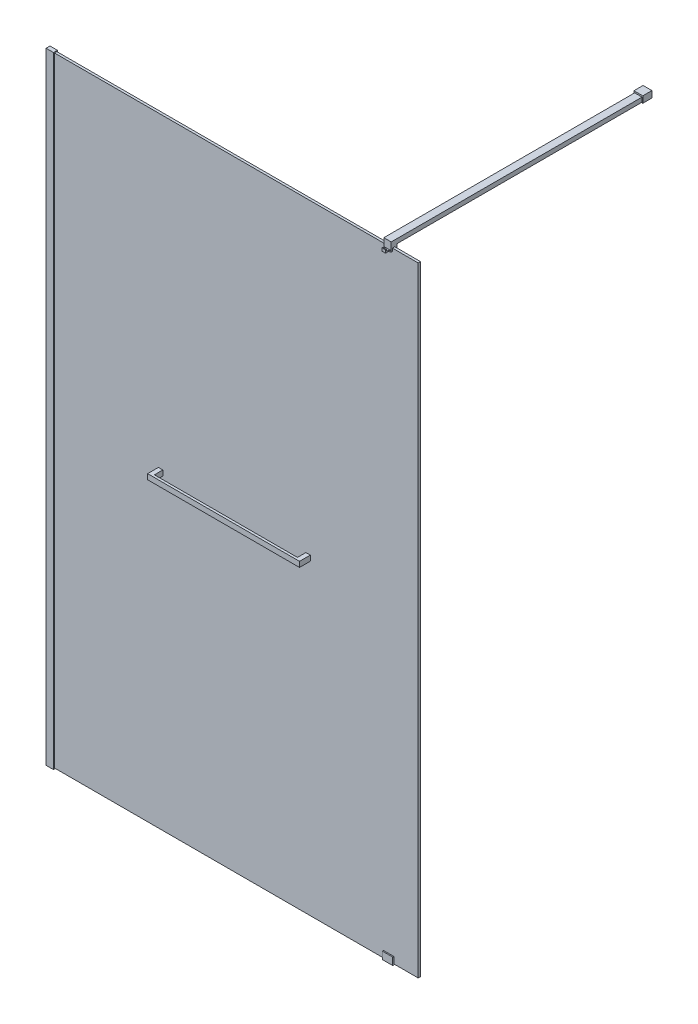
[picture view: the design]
ISO-10303-21;
HEADER;
FILE_DESCRIPTION(('STEP AP214'),'2;1');
FILE_NAME('part.step','',(''),(''),'','','');
FILE_SCHEMA(('AUTOMOTIVE_DESIGN { 1 0 10303 214 1 1 1 1 }'));
ENDSEC;
DATA;
#1=APPLICATION_CONTEXT('core data for automotive mechanical design processes');
#2=APPLICATION_PROTOCOL_DEFINITION('international standard','automotive_design',2000,#1);
#3=PRODUCT_CONTEXT('',#1,'mechanical');
#4=PRODUCT('Part','Part','',(#3));
#5=PRODUCT_RELATED_PRODUCT_CATEGORY('part','',(#4));
#6=PRODUCT_DEFINITION_FORMATION('','',#4);
#7=PRODUCT_DEFINITION_CONTEXT('part definition',#1,'design');
#8=PRODUCT_DEFINITION('design','',#6,#7);
#9=PRODUCT_DEFINITION_SHAPE('','',#8);
#10=(LENGTH_UNIT() NAMED_UNIT(*) SI_UNIT(.MILLI.,.METRE.));
#11=(NAMED_UNIT(*) PLANE_ANGLE_UNIT() SI_UNIT($,.RADIAN.));
#12=(NAMED_UNIT(*) SI_UNIT($,.STERADIAN.) SOLID_ANGLE_UNIT());
#13=UNCERTAINTY_MEASURE_WITH_UNIT(LENGTH_MEASURE(1.E-05),#10,'distance_accuracy_value','');
#14=(GEOMETRIC_REPRESENTATION_CONTEXT(3) GLOBAL_UNCERTAINTY_ASSIGNED_CONTEXT((#13)) GLOBAL_UNIT_ASSIGNED_CONTEXT((#10,
#11,#12)) REPRESENTATION_CONTEXT('',''));
#15=CARTESIAN_POINT('',(0.,0.,0.));
#16=DIRECTION('',(0.,0.,1.));
#17=DIRECTION('',(1.,0.,0.));
#18=AXIS2_PLACEMENT_3D('',#15,#16,#17);
#19=CARTESIAN_POINT('',(392.45,1059.,-21.4));
#20=DIRECTION('',(1.,0.,0.));
#21=DIRECTION('',(0.,0.,-1.));
#22=AXIS2_PLACEMENT_3D('',#19,#20,#21);
#23=PLANE('',#22);
#24=DIRECTION('',(0.,1.,0.));
#25=VECTOR('',#24,1.);
#26=CARTESIAN_POINT('',(392.45,1059.,25.1));
#27=LINE('',#26,#25);
#28=CARTESIAN_POINT('',(392.45,1041.,25.1));
#29=VERTEX_POINT('',#28);
#30=CARTESIAN_POINT('',(392.45,1059.,25.1));
#31=VERTEX_POINT('',#30);
#32=EDGE_CURVE('E63',#29,#31,#27,.T.);
#33=ORIENTED_EDGE('',*,*,#32,.F.);
#34=DIRECTION('',(0.,0.,1.));
#35=VECTOR('',#34,1.);
#36=CARTESIAN_POINT('',(392.45,1041.,-21.4));
#37=LINE('',#36,#35);
#38=CARTESIAN_POINT('',(392.45,1041.,-21.4));
#39=VERTEX_POINT('',#38);
#40=EDGE_CURVE('E12',#39,#29,#37,.T.);
#41=ORIENTED_EDGE('',*,*,#40,.F.);
#42=DIRECTION('',(0.,1.,0.));
#43=VECTOR('',#42,1.);
#44=CARTESIAN_POINT('',(392.45,1059.,-21.4));
#45=LINE('',#44,#43);
#46=CARTESIAN_POINT('',(392.45,1059.,-21.4));
#47=VERTEX_POINT('',#46);
#48=EDGE_CURVE('E193',#39,#47,#45,.T.);
#49=ORIENTED_EDGE('',*,*,#48,.T.);
#50=DIRECTION('',(0.,0.,1.));
#51=VECTOR('',#50,1.);
#52=CARTESIAN_POINT('',(392.45,1059.,-21.4));
#53=LINE('',#52,#51);
#54=EDGE_CURVE('E176',#47,#31,#53,.T.);
#55=ORIENTED_EDGE('',*,*,#54,.T.);
#56=EDGE_LOOP('',(#33,#41,#49,#55));
#57=FACE_BOUND('',#56,.T.);
#58=ADVANCED_FACE('F46',(#57),#23,.T.);
#59=CARTESIAN_POINT('',(377.45,1041.,-21.4));
#60=DIRECTION('',(0.,-1.,0.));
#61=DIRECTION('',(0.,0.,-1.));
#62=AXIS2_PLACEMENT_3D('',#59,#60,#61);
#63=PLANE('',#62);
#64=ORIENTED_EDGE('',*,*,#40,.T.);
#65=DIRECTION('',(-1.,0.,0.));
#66=VECTOR('',#65,1.);
#67=CARTESIAN_POINT('',(897.147715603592,1041.,25.1));
#68=LINE('',#67,#66);
#69=CARTESIAN_POINT('',(877.45,1041.,25.1));
#70=VERTEX_POINT('',#69);
#71=EDGE_CURVE('E166',#70,#29,#68,.T.);
#72=ORIENTED_EDGE('',*,*,#71,.F.);
#73=DIRECTION('',(0.,0.,1.));
#74=VECTOR('',#73,1.);
#75=CARTESIAN_POINT('',(877.45,1041.,-21.4));
#76=LINE('',#75,#74);
#77=CARTESIAN_POINT('',(877.45,1041.,-21.4));
#78=VERTEX_POINT('',#77);
#79=EDGE_CURVE('E149',#78,#70,#76,.T.);
#80=ORIENTED_EDGE('',*,*,#79,.F.);
#81=DIRECTION('',(1.,0.,0.));
#82=VECTOR('',#81,1.);
#83=CARTESIAN_POINT('',(877.45,1041.,-21.4));
#84=LINE('',#83,#82);
#85=CARTESIAN_POINT('',(892.45,1041.,-21.4));
#86=VERTEX_POINT('',#85);
#87=EDGE_CURVE('E131',#78,#86,#84,.T.);
#88=ORIENTED_EDGE('',*,*,#87,.T.);
#89=DIRECTION('',(0.,0.,1.));
#90=VECTOR('',#89,1.);
#91=CARTESIAN_POINT('',(892.45,1041.,-21.4));
#92=LINE('',#91,#90);
#93=CARTESIAN_POINT('',(892.45,1041.,33.1));
#94=VERTEX_POINT('',#93);
#95=EDGE_CURVE('E147',#86,#94,#92,.T.);
#96=ORIENTED_EDGE('',*,*,#95,.T.);
#97=DIRECTION('',(1.,0.,0.));
#98=VECTOR('',#97,1.);
#99=CARTESIAN_POINT('',(377.45,1041.,33.1));
#100=LINE('',#99,#98);
#101=CARTESIAN_POINT('',(377.45,1041.,33.1));
#102=VERTEX_POINT('',#101);
#103=EDGE_CURVE('E135',#102,#94,#100,.T.);
#104=ORIENTED_EDGE('',*,*,#103,.F.);
#105=DIRECTION('',(0.,0.,1.));
#106=VECTOR('',#105,1.);
#107=CARTESIAN_POINT('',(377.45,1041.,-21.4));
#108=LINE('',#107,#106);
#109=CARTESIAN_POINT('',(377.45,1041.,-21.4));
#110=VERTEX_POINT('',#109);
#111=EDGE_CURVE('E55',#110,#102,#108,.T.);
#112=ORIENTED_EDGE('',*,*,#111,.F.);
#113=DIRECTION('',(1.,0.,0.));
#114=VECTOR('',#113,1.);
#115=CARTESIAN_POINT('',(377.45,1041.,-21.4));
#116=LINE('',#115,#114);
#117=EDGE_CURVE('E181',#110,#39,#116,.T.);
#118=ORIENTED_EDGE('',*,*,#117,.T.);
#119=EDGE_LOOP('',(#64,#72,#80,#88,#96,#104,#112,#118));
#120=FACE_BOUND('',#119,.T.);
#121=ADVANCED_FACE('F197',(#120),#63,.T.);
#122=CARTESIAN_POINT('',(377.45,1059.,-21.4));
#123=DIRECTION('',(-1.,0.,0.));
#124=DIRECTION('',(0.,0.,1.));
#125=AXIS2_PLACEMENT_3D('',#122,#123,#124);
#126=PLANE('',#125);
#127=ORIENTED_EDGE('',*,*,#111,.T.);
#128=DIRECTION('',(0.,-1.,0.));
#129=VECTOR('',#128,1.);
#130=CARTESIAN_POINT('',(377.45,1059.,33.1));
#131=LINE('',#130,#129);
#132=CARTESIAN_POINT('',(377.45,1059.,33.1));
#133=VERTEX_POINT('',#132);
#134=EDGE_CURVE('E121',#133,#102,#131,.T.);
#135=ORIENTED_EDGE('',*,*,#134,.F.);
#136=DIRECTION('',(0.,0.,1.));
#137=VECTOR('',#136,1.);
#138=CARTESIAN_POINT('',(377.45,1059.,-21.4));
#139=LINE('',#138,#137);
#140=CARTESIAN_POINT('',(377.45,1059.,-21.4));
#141=VERTEX_POINT('',#140);
#142=EDGE_CURVE('E116',#141,#133,#139,.T.);
#143=ORIENTED_EDGE('',*,*,#142,.F.);
#144=DIRECTION('',(0.,-1.,0.));
#145=VECTOR('',#144,1.);
#146=CARTESIAN_POINT('',(377.45,1059.,-21.4));
#147=LINE('',#146,#145);
#148=EDGE_CURVE('E186',#141,#110,#147,.T.);
#149=ORIENTED_EDGE('',*,*,#148,.T.);
#150=EDGE_LOOP('',(#127,#135,#143,#149));
#151=FACE_BOUND('',#150,.T.);
#152=ADVANCED_FACE('F218',(#151),#126,.T.);
#153=CARTESIAN_POINT('',(377.45,1059.,-21.4));
#154=DIRECTION('',(0.,1.,0.));
#155=DIRECTION('',(0.,0.,1.));
#156=AXIS2_PLACEMENT_3D('',#153,#154,#155);
#157=PLANE('',#156);
#158=ORIENTED_EDGE('',*,*,#142,.T.);
#159=DIRECTION('',(-1.,0.,0.));
#160=VECTOR('',#159,1.);
#161=CARTESIAN_POINT('',(377.45,1059.,33.1));
#162=LINE('',#161,#160);
#163=CARTESIAN_POINT('',(892.45,1059.,33.1));
#164=VERTEX_POINT('',#163);
#165=EDGE_CURVE('E109',#164,#133,#162,.T.);
#166=ORIENTED_EDGE('',*,*,#165,.F.);
#167=DIRECTION('',(0.,0.,1.));
#168=VECTOR('',#167,1.);
#169=CARTESIAN_POINT('',(892.45,1059.,-21.4));
#170=LINE('',#169,#168);
#171=CARTESIAN_POINT('',(892.45,1059.,-21.4));
#172=VERTEX_POINT('',#171);
#173=EDGE_CURVE('E113',#172,#164,#170,.T.);
#174=ORIENTED_EDGE('',*,*,#173,.F.);
#175=DIRECTION('',(-1.,0.,0.));
#176=VECTOR('',#175,1.);
#177=CARTESIAN_POINT('',(877.45,1059.,-21.4));
#178=LINE('',#177,#176);
#179=CARTESIAN_POINT('',(877.45,1059.,-21.4));
#180=VERTEX_POINT('',#179);
#181=EDGE_CURVE('E138',#172,#180,#178,.T.);
#182=ORIENTED_EDGE('',*,*,#181,.T.);
#183=DIRECTION('',(0.,0.,1.));
#184=VECTOR('',#183,1.);
#185=CARTESIAN_POINT('',(877.45,1059.,-21.4));
#186=LINE('',#185,#184);
#187=CARTESIAN_POINT('',(877.45,1059.,25.1));
#188=VERTEX_POINT('',#187);
#189=EDGE_CURVE('E130',#180,#188,#186,.T.);
#190=ORIENTED_EDGE('',*,*,#189,.T.);
#191=DIRECTION('',(-1.,0.,0.));
#192=VECTOR('',#191,1.);
#193=CARTESIAN_POINT('',(897.147715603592,1059.,25.1));
#194=LINE('',#193,#192);
#195=EDGE_CURVE('E163',#188,#31,#194,.T.);
#196=ORIENTED_EDGE('',*,*,#195,.T.);
#197=ORIENTED_EDGE('',*,*,#54,.F.);
#198=DIRECTION('',(-1.,0.,0.));
#199=VECTOR('',#198,1.);
#200=CARTESIAN_POINT('',(377.45,1059.,-21.4));
#201=LINE('',#200,#199);
#202=EDGE_CURVE('E190',#47,#141,#201,.T.);
#203=ORIENTED_EDGE('',*,*,#202,.T.);
#204=EDGE_LOOP('',(#158,#166,#174,#182,#190,#196,#197,#203));
#205=FACE_BOUND('',#204,.T.);
#206=ADVANCED_FACE('F111',(#205),#157,.T.);
#207=CARTESIAN_POINT('',(392.45,1041.,-21.4));
#208=DIRECTION('',(0.,0.,1.));
#209=DIRECTION('',(1.,0.,0.));
#210=AXIS2_PLACEMENT_3D('',#207,#208,#209);
#211=PLANE('',#210);
#212=ORIENTED_EDGE('',*,*,#48,.F.);
#213=ORIENTED_EDGE('',*,*,#117,.F.);
#214=ORIENTED_EDGE('',*,*,#148,.F.);
#215=ORIENTED_EDGE('',*,*,#202,.F.);
#216=EDGE_LOOP('',(#212,#213,#214,#215));
#217=FACE_BOUND('',#216,.T.);
#218=ADVANCED_FACE('F225',(#217),#211,.F.);
#219=CARTESIAN_POINT('',(392.45,1041.,33.1));
#220=DIRECTION('',(0.,0.,1.));
#221=DIRECTION('',(1.,0.,0.));
#222=AXIS2_PLACEMENT_3D('',#219,#220,#221);
#223=PLANE('',#222);
#224=ORIENTED_EDGE('',*,*,#103,.T.);
#225=DIRECTION('',(0.,1.,0.));
#226=VECTOR('',#225,1.);
#227=CARTESIAN_POINT('',(892.45,1059.,33.1));
#228=LINE('',#227,#226);
#229=EDGE_CURVE('E127',#94,#164,#228,.T.);
#230=ORIENTED_EDGE('',*,*,#229,.T.);
#231=ORIENTED_EDGE('',*,*,#165,.T.);
#232=ORIENTED_EDGE('',*,*,#134,.T.);
#233=EDGE_LOOP('',(#224,#230,#231,#232));
#234=FACE_BOUND('',#233,.T.);
#235=ADVANCED_FACE('F133',(#234),#223,.T.);
#236=CARTESIAN_POINT('',(897.147715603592,1059.,25.1));
#237=DIRECTION('',(0.,0.,1.));
#238=DIRECTION('',(0.,-1.,0.));
#239=AXIS2_PLACEMENT_3D('',#236,#237,#238);
#240=PLANE('',#239);
#241=ORIENTED_EDGE('',*,*,#195,.F.);
#242=DIRECTION('',(0.,-1.,0.));
#243=VECTOR('',#242,1.);
#244=CARTESIAN_POINT('',(877.45,1059.,25.1));
#245=LINE('',#244,#243);
#246=EDGE_CURVE('E49',#188,#70,#245,.T.);
#247=ORIENTED_EDGE('',*,*,#246,.T.);
#248=ORIENTED_EDGE('',*,*,#71,.T.);
#249=ORIENTED_EDGE('',*,*,#32,.T.);
#250=EDGE_LOOP('',(#241,#247,#248,#249));
#251=FACE_BOUND('',#250,.T.);
#252=ADVANCED_FACE('F203',(#251),#240,.F.);
#253=CARTESIAN_POINT('',(877.45,1059.,-21.4));
#254=DIRECTION('',(-1.,0.,0.));
#255=DIRECTION('',(0.,0.,1.));
#256=AXIS2_PLACEMENT_3D('',#253,#254,#255);
#257=PLANE('',#256);
#258=ORIENTED_EDGE('',*,*,#246,.F.);
#259=ORIENTED_EDGE('',*,*,#189,.F.);
#260=DIRECTION('',(0.,-1.,0.));
#261=VECTOR('',#260,1.);
#262=CARTESIAN_POINT('',(877.45,1059.,-21.4));
#263=LINE('',#262,#261);
#264=EDGE_CURVE('E142',#180,#78,#263,.T.);
#265=ORIENTED_EDGE('',*,*,#264,.T.);
#266=ORIENTED_EDGE('',*,*,#79,.T.);
#267=EDGE_LOOP('',(#258,#259,#265,#266));
#268=FACE_BOUND('',#267,.T.);
#269=ADVANCED_FACE('F204',(#268),#257,.T.);
#270=CARTESIAN_POINT('',(892.45,1059.,-21.4));
#271=DIRECTION('',(1.,0.,0.));
#272=DIRECTION('',(0.,0.,-1.));
#273=AXIS2_PLACEMENT_3D('',#270,#271,#272);
#274=PLANE('',#273);
#275=ORIENTED_EDGE('',*,*,#173,.T.);
#276=ORIENTED_EDGE('',*,*,#229,.F.);
#277=ORIENTED_EDGE('',*,*,#95,.F.);
#278=DIRECTION('',(0.,1.,0.));
#279=VECTOR('',#278,1.);
#280=CARTESIAN_POINT('',(892.45,1059.,-21.4));
#281=LINE('',#280,#279);
#282=EDGE_CURVE('E129',#86,#172,#281,.T.);
#283=ORIENTED_EDGE('',*,*,#282,.T.);
#284=EDGE_LOOP('',(#275,#276,#277,#283));
#285=FACE_BOUND('',#284,.T.);
#286=ADVANCED_FACE('F126',(#285),#274,.T.);
#287=CARTESIAN_POINT('',(892.45,1041.,-21.4));
#288=DIRECTION('',(0.,0.,1.));
#289=DIRECTION('',(1.,0.,0.));
#290=AXIS2_PLACEMENT_3D('',#287,#288,#289);
#291=PLANE('',#290);
#292=ORIENTED_EDGE('',*,*,#282,.F.);
#293=ORIENTED_EDGE('',*,*,#87,.F.);
#294=ORIENTED_EDGE('',*,*,#264,.F.);
#295=ORIENTED_EDGE('',*,*,#181,.F.);
#296=EDGE_LOOP('',(#292,#293,#294,#295));
#297=FACE_BOUND('',#296,.T.);
#298=ADVANCED_FACE('F200',(#297),#291,.F.);
#299=CLOSED_SHELL('',(#58,#121,#152,#206,#218,#235,#252,#269,#286,#298));
#300=MANIFOLD_SOLID_BREP('B2',#299);
#301=CARTESIAN_POINT('',(1170.95,2090.,-19.4000000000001));
#302=DIRECTION('',(-1.,0.,0.));
#303=DIRECTION('',(0.,0.,1.));
#304=AXIS2_PLACEMENT_3D('',#301,#302,#303);
#305=PLANE('',#304);
#306=DIRECTION('',(0.,-1.,0.));
#307=VECTOR('',#306,1.);
#308=CARTESIAN_POINT('',(1170.95,2090.,-850.03));
#309=LINE('',#308,#307);
#310=CARTESIAN_POINT('',(1170.95,2120.,-850.03));
#311=VERTEX_POINT('',#310);
#312=CARTESIAN_POINT('',(1170.95,2105.,-850.03));
#313=VERTEX_POINT('',#312);
#314=EDGE_CURVE('E333',#311,#313,#309,.T.);
#315=ORIENTED_EDGE('',*,*,#314,.F.);
#316=DIRECTION('',(0.,0.,1.));
#317=VECTOR('',#316,1.);
#318=CARTESIAN_POINT('',(1170.95,2120.,0.599999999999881));
#319=LINE('',#318,#317);
#320=CARTESIAN_POINT('',(1170.95,2120.,0.599999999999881));
#321=VERTEX_POINT('',#320);
#322=EDGE_CURVE('E658',#311,#321,#319,.T.);
#323=ORIENTED_EDGE('',*,*,#322,.T.);
#324=DIRECTION('',(0.,-1.,0.));
#325=VECTOR('',#324,1.);
#326=CARTESIAN_POINT('',(1170.95,2094.,0.599999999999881));
#327=LINE('',#326,#325);
#328=CARTESIAN_POINT('',(1170.95,2094.,0.599999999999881));
#329=VERTEX_POINT('',#328);
#330=EDGE_CURVE('E660',#321,#329,#327,.T.);
#331=ORIENTED_EDGE('',*,*,#330,.T.);
#332=DIRECTION('',(0.,1.,0.));
#333=VECTOR('',#332,1.);
#334=CARTESIAN_POINT('',(1170.95,2090.,0.599999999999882));
#335=LINE('',#334,#333);
#336=CARTESIAN_POINT('',(1170.95,2090.,0.599999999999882));
#337=VERTEX_POINT('',#336);
#338=EDGE_CURVE('E604',#337,#329,#335,.T.);
#339=ORIENTED_EDGE('',*,*,#338,.F.);
#340=DIRECTION('',(0.,0.,-1.));
#341=VECTOR('',#340,1.);
#342=CARTESIAN_POINT('',(1170.95,2090.,-3.40000000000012));
#343=LINE('',#342,#341);
#344=CARTESIAN_POINT('',(1170.95,2090.,-3.40000000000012));
#345=VERTEX_POINT('',#344);
#346=EDGE_CURVE('E634',#337,#345,#343,.T.);
#347=ORIENTED_EDGE('',*,*,#346,.T.);
#348=DIRECTION('',(0.,1.,-1.30407837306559E-13));
#349=VECTOR('',#348,1.);
#350=CARTESIAN_POINT('',(1170.95,2100.,-3.40000000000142));
#351=LINE('',#350,#349);
#352=CARTESIAN_POINT('',(1170.95,2100.,-3.40000000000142));
#353=VERTEX_POINT('',#352);
#354=EDGE_CURVE('E664',#345,#353,#351,.T.);
#355=ORIENTED_EDGE('',*,*,#354,.T.);
#356=DIRECTION('',(0.,0.,-1.));
#357=VECTOR('',#356,1.);
#358=CARTESIAN_POINT('',(1170.95,2100.,-11.4000000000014));
#359=LINE('',#358,#357);
#360=CARTESIAN_POINT('',(1170.95,2100.,-11.4000000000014));
#361=VERTEX_POINT('',#360);
#362=EDGE_CURVE('E666',#353,#361,#359,.T.);
#363=ORIENTED_EDGE('',*,*,#362,.T.);
#364=DIRECTION('',(0.,-1.,1.30451205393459E-13));
#365=VECTOR('',#364,1.);
#366=CARTESIAN_POINT('',(1170.95,2090.,-11.4000000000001));
#367=LINE('',#366,#365);
#368=CARTESIAN_POINT('',(1170.95,2090.,-11.4000000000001));
#369=VERTEX_POINT('',#368);
#370=EDGE_CURVE('E667',#361,#369,#367,.T.);
#371=ORIENTED_EDGE('',*,*,#370,.T.);
#372=DIRECTION('',(0.,0.,-1.));
#373=VECTOR('',#372,1.);
#374=CARTESIAN_POINT('',(1170.95,2090.,-19.4000000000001));
#375=LINE('',#374,#373);
#376=CARTESIAN_POINT('',(1170.95,2090.,-19.4000000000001));
#377=VERTEX_POINT('',#376);
#378=EDGE_CURVE('E555',#369,#377,#375,.T.);
#379=ORIENTED_EDGE('',*,*,#378,.T.);
#380=DIRECTION('',(0.,1.,0.));
#381=VECTOR('',#380,1.);
#382=CARTESIAN_POINT('',(1170.95,2120.,-19.4000000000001));
#383=LINE('',#382,#381);
#384=CARTESIAN_POINT('',(1170.95,2105.,-19.4000000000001));
#385=VERTEX_POINT('',#384);
#386=EDGE_CURVE('E521',#377,#385,#383,.T.);
#387=ORIENTED_EDGE('',*,*,#386,.T.);
#388=DIRECTION('',(0.,0.,-1.));
#389=VECTOR('',#388,1.);
#390=CARTESIAN_POINT('',(1170.95,2105.,-881.03));
#391=LINE('',#390,#389);
#392=EDGE_CURVE('E520',#385,#313,#391,.T.);
#393=ORIENTED_EDGE('',*,*,#392,.T.);
#394=EDGE_LOOP('',(#315,#323,#331,#339,#347,#355,#363,#371,#379,#387,#393));
#395=FACE_BOUND('',#394,.T.);
#396=ADVANCED_FACE('F318',(#395),#305,.F.);
#397=CARTESIAN_POINT('',(1145.95,2090.,-19.4000000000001));
#398=DIRECTION('',(-1.,0.,0.));
#399=DIRECTION('',(0.,0.,1.));
#400=AXIS2_PLACEMENT_3D('',#397,#398,#399);
#401=PLANE('',#400);
#402=DIRECTION('',(0.,0.,1.));
#403=VECTOR('',#402,1.);
#404=CARTESIAN_POINT('',(1145.95,2120.,0.599999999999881));
#405=LINE('',#404,#403);
#406=CARTESIAN_POINT('',(1145.95,2120.,-850.03));
#407=VERTEX_POINT('',#406);
#408=CARTESIAN_POINT('',(1145.95,2120.,0.599999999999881));
#409=VERTEX_POINT('',#408);
#410=EDGE_CURVE('E544',#407,#409,#405,.T.);
#411=ORIENTED_EDGE('',*,*,#410,.F.);
#412=DIRECTION('',(0.,-1.,0.));
#413=VECTOR('',#412,1.);
#414=CARTESIAN_POINT('',(1145.95,2090.,-850.03));
#415=LINE('',#414,#413);
#416=CARTESIAN_POINT('',(1145.95,2105.,-850.03));
#417=VERTEX_POINT('',#416);
#418=EDGE_CURVE('E502',#407,#417,#415,.T.);
#419=ORIENTED_EDGE('',*,*,#418,.T.);
#420=DIRECTION('',(0.,0.,1.));
#421=VECTOR('',#420,1.);
#422=CARTESIAN_POINT('',(1145.95,2105.,-881.03));
#423=LINE('',#422,#421);
#424=CARTESIAN_POINT('',(1145.95,2105.,-19.4000000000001));
#425=VERTEX_POINT('',#424);
#426=EDGE_CURVE('E510',#417,#425,#423,.T.);
#427=ORIENTED_EDGE('',*,*,#426,.T.);
#428=DIRECTION('',(0.,1.,0.));
#429=VECTOR('',#428,1.);
#430=CARTESIAN_POINT('',(1145.95,2120.,-19.4000000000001));
#431=LINE('',#430,#429);
#432=CARTESIAN_POINT('',(1145.95,2090.,-19.4000000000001));
#433=VERTEX_POINT('',#432);
#434=EDGE_CURVE('E534',#433,#425,#431,.T.);
#435=ORIENTED_EDGE('',*,*,#434,.F.);
#436=DIRECTION('',(0.,0.,-1.));
#437=VECTOR('',#436,1.);
#438=CARTESIAN_POINT('',(1145.95,2090.,-19.4000000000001));
#439=LINE('',#438,#437);
#440=CARTESIAN_POINT('',(1145.95,2090.,-11.4000000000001));
#441=VERTEX_POINT('',#440);
#442=EDGE_CURVE('E568',#441,#433,#439,.T.);
#443=ORIENTED_EDGE('',*,*,#442,.F.);
#444=DIRECTION('',(0.,-1.,1.30451205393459E-13));
#445=VECTOR('',#444,1.);
#446=CARTESIAN_POINT('',(1145.95,2090.,-11.4000000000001));
#447=LINE('',#446,#445);
#448=CARTESIAN_POINT('',(1145.95,2100.,-11.4000000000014));
#449=VERTEX_POINT('',#448);
#450=EDGE_CURVE('E566',#449,#441,#447,.T.);
#451=ORIENTED_EDGE('',*,*,#450,.F.);
#452=DIRECTION('',(0.,0.,-1.));
#453=VECTOR('',#452,1.);
#454=CARTESIAN_POINT('',(1145.95,2100.,-11.4000000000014));
#455=LINE('',#454,#453);
#456=CARTESIAN_POINT('',(1145.95,2100.,-3.40000000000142));
#457=VERTEX_POINT('',#456);
#458=EDGE_CURVE('E564',#457,#449,#455,.T.);
#459=ORIENTED_EDGE('',*,*,#458,.F.);
#460=DIRECTION('',(0.,1.,-1.30407837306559E-13));
#461=VECTOR('',#460,1.);
#462=CARTESIAN_POINT('',(1145.95,2100.,-3.40000000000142));
#463=LINE('',#462,#461);
#464=CARTESIAN_POINT('',(1145.95,2090.,-3.40000000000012));
#465=VERTEX_POINT('',#464);
#466=EDGE_CURVE('E562',#465,#457,#463,.T.);
#467=ORIENTED_EDGE('',*,*,#466,.F.);
#468=DIRECTION('',(0.,0.,-1.));
#469=VECTOR('',#468,1.);
#470=CARTESIAN_POINT('',(1145.95,2090.,-3.40000000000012));
#471=LINE('',#470,#469);
#472=CARTESIAN_POINT('',(1145.95,2090.,0.599999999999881));
#473=VERTEX_POINT('',#472);
#474=EDGE_CURVE('E560',#473,#465,#471,.T.);
#475=ORIENTED_EDGE('',*,*,#474,.F.);
#476=DIRECTION('',(0.,1.,0.));
#477=VECTOR('',#476,1.);
#478=CARTESIAN_POINT('',(1145.95,2090.,0.599999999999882));
#479=LINE('',#478,#477);
#480=CARTESIAN_POINT('',(1145.95,2094.,0.599999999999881));
#481=VERTEX_POINT('',#480);
#482=EDGE_CURVE('E601',#473,#481,#479,.T.);
#483=ORIENTED_EDGE('',*,*,#482,.T.);
#484=DIRECTION('',(0.,-1.,0.));
#485=VECTOR('',#484,1.);
#486=CARTESIAN_POINT('',(1145.95,2094.,0.599999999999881));
#487=LINE('',#486,#485);
#488=EDGE_CURVE('E546',#409,#481,#487,.T.);
#489=ORIENTED_EDGE('',*,*,#488,.F.);
#490=EDGE_LOOP('',(#411,#419,#427,#435,#443,#451,#459,#467,#475,#483,#489));
#491=FACE_BOUND('',#490,.T.);
#492=ADVANCED_FACE('F531',(#491),#401,.T.);
#493=CARTESIAN_POINT('',(1170.95,2120.,0.599999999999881));
#494=DIRECTION('',(0.,-1.,0.));
#495=DIRECTION('',(0.,0.,-1.));
#496=AXIS2_PLACEMENT_3D('',#493,#494,#495);
#497=PLANE('',#496);
#498=DIRECTION('',(1.,0.,0.));
#499=VECTOR('',#498,1.);
#500=CARTESIAN_POINT('',(1170.95,2120.,-850.03));
#501=LINE('',#500,#499);
#502=EDGE_CURVE('E340',#407,#311,#501,.T.);
#503=ORIENTED_EDGE('',*,*,#502,.F.);
#504=ORIENTED_EDGE('',*,*,#410,.T.);
#505=DIRECTION('',(-1.,0.,0.));
#506=VECTOR('',#505,1.);
#507=CARTESIAN_POINT('',(1170.95,2120.,0.599999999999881));
#508=LINE('',#507,#506);
#509=EDGE_CURVE('E598',#321,#409,#508,.T.);
#510=ORIENTED_EDGE('',*,*,#509,.F.);
#511=ORIENTED_EDGE('',*,*,#322,.F.);
#512=EDGE_LOOP('',(#503,#504,#510,#511));
#513=FACE_BOUND('',#512,.T.);
#514=ADVANCED_FACE('F709',(#513),#497,.F.);
#515=CARTESIAN_POINT('',(1145.95,2105.,-19.4000000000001));
#516=DIRECTION('',(0.,1.,0.));
#517=DIRECTION('',(0.,0.,1.));
#518=AXIS2_PLACEMENT_3D('',#515,#516,#517);
#519=PLANE('',#518);
#520=DIRECTION('',(-1.,0.,0.));
#521=VECTOR('',#520,1.);
#522=CARTESIAN_POINT('',(1145.95,2105.,-850.03));
#523=LINE('',#522,#521);
#524=EDGE_CURVE('E44',#313,#417,#523,.T.);
#525=ORIENTED_EDGE('',*,*,#524,.F.);
#526=ORIENTED_EDGE('',*,*,#392,.F.);
#527=DIRECTION('',(1.,0.,0.));
#528=VECTOR('',#527,1.);
#529=CARTESIAN_POINT('',(1145.95,2105.,-19.4000000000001));
#530=LINE('',#529,#528);
#531=EDGE_CURVE('E516',#425,#385,#530,.T.);
#532=ORIENTED_EDGE('',*,*,#531,.F.);
#533=ORIENTED_EDGE('',*,*,#426,.F.);
#534=EDGE_LOOP('',(#525,#526,#532,#533));
#535=FACE_BOUND('',#534,.T.);
#536=ADVANCED_FACE('F537',(#535),#519,.F.);
#537=CARTESIAN_POINT('',(1170.95,2094.,9.84506801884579));
#538=DIRECTION('',(0.,-1.,0.));
#539=DIRECTION('',(0.,0.,-1.));
#540=AXIS2_PLACEMENT_3D('',#537,#538,#539);
#541=PLANE('',#540);
#542=DIRECTION('',(-0.906307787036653,0.,-0.422618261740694));
#543=VECTOR('',#542,1.);
#544=CARTESIAN_POINT('',(1170.02591161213,2094.,11.8267819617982));
#545=LINE('',#544,#543);
#546=CARTESIAN_POINT('',(1152.45,2094.,3.6309997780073));
#547=VERTEX_POINT('',#546);
#548=EDGE_CURVE('E637',#547,#481,#545,.T.);
#549=ORIENTED_EDGE('',*,*,#548,.F.);
#550=DIRECTION('',(0.,0.,-1.));
#551=VECTOR('',#550,1.);
#552=CARTESIAN_POINT('',(1152.45,2094.,9.84506801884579));
#553=LINE('',#552,#551);
#554=CARTESIAN_POINT('',(1152.45,2094.,9.84506801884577));
#555=VERTEX_POINT('',#554);
#556=EDGE_CURVE('E545',#555,#547,#553,.T.);
#557=ORIENTED_EDGE('',*,*,#556,.F.);
#558=DIRECTION('',(-1.,0.,0.));
#559=VECTOR('',#558,1.);
#560=CARTESIAN_POINT('',(1170.95,2094.,9.84506801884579));
#561=LINE('',#560,#559);
#562=CARTESIAN_POINT('',(1164.45,2094.,9.84506801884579));
#563=VERTEX_POINT('',#562);
#564=EDGE_CURVE('E592',#563,#555,#561,.T.);
#565=ORIENTED_EDGE('',*,*,#564,.F.);
#566=DIRECTION('',(0.,0.,1.));
#567=VECTOR('',#566,1.);
#568=CARTESIAN_POINT('',(1164.45,2094.,9.84506801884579));
#569=LINE('',#568,#567);
#570=CARTESIAN_POINT('',(1164.45,2094.,3.63099977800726));
#571=VERTEX_POINT('',#570);
#572=EDGE_CURVE('E651',#571,#563,#569,.T.);
#573=ORIENTED_EDGE('',*,*,#572,.F.);
#574=DIRECTION('',(-0.906307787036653,0.,0.422618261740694));
#575=VECTOR('',#574,1.);
#576=CARTESIAN_POINT('',(1167.40893350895,2094.,2.25122642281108));
#577=LINE('',#576,#575);
#578=EDGE_CURVE('E636',#329,#571,#577,.T.);
#579=ORIENTED_EDGE('',*,*,#578,.F.);
#580=DIRECTION('',(-1.,0.,0.));
#581=VECTOR('',#580,1.);
#582=CARTESIAN_POINT('',(1170.95,2094.,0.599999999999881));
#583=LINE('',#582,#581);
#584=EDGE_CURVE('E595',#329,#481,#583,.T.);
#585=ORIENTED_EDGE('',*,*,#584,.T.);
#586=EDGE_LOOP('',(#549,#557,#565,#573,#579,#585));
#587=FACE_BOUND('',#586,.T.);
#588=ADVANCED_FACE('F696',(#587),#541,.F.);
#589=CARTESIAN_POINT('',(1170.95,2100.,10.3700000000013));
#590=DIRECTION('',(0.,-0.087155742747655,0.996194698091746));
#591=DIRECTION('',(0.,-0.996194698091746,-0.087155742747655));
#592=AXIS2_PLACEMENT_3D('',#589,#590,#591);
#593=PLANE('',#592);
#594=DIRECTION('',(0.,-0.996194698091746,-0.087155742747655));
#595=VECTOR('',#594,1.);
#596=CARTESIAN_POINT('',(1152.45,2100.,10.3700000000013));
#597=LINE('',#596,#595);
#598=CARTESIAN_POINT('',(1152.45,2100.,10.3700000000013));
#599=VERTEX_POINT('',#598);
#600=EDGE_CURVE('E548',#599,#555,#597,.T.);
#601=ORIENTED_EDGE('',*,*,#600,.F.);
#602=DIRECTION('',(-1.,0.,0.));
#603=VECTOR('',#602,1.);
#604=CARTESIAN_POINT('',(1170.95,2100.,10.3700000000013));
#605=LINE('',#604,#603);
#606=CARTESIAN_POINT('',(1164.45,2100.,10.3700000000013));
#607=VERTEX_POINT('',#606);
#608=EDGE_CURVE('E589',#607,#599,#605,.T.);
#609=ORIENTED_EDGE('',*,*,#608,.F.);
#610=DIRECTION('',(0.,0.996194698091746,0.087155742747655));
#611=VECTOR('',#610,1.);
#612=CARTESIAN_POINT('',(1164.45,2100.,10.3700000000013));
#613=LINE('',#612,#611);
#614=EDGE_CURVE('E648',#563,#607,#613,.T.);
#615=ORIENTED_EDGE('',*,*,#614,.F.);
#616=ORIENTED_EDGE('',*,*,#564,.T.);
#617=EDGE_LOOP('',(#601,#609,#615,#616));
#618=FACE_BOUND('',#617,.T.);
#619=ADVANCED_FACE('F700',(#618),#593,.F.);
#620=CARTESIAN_POINT('',(1170.95,2100.,13.3700000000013));
#621=DIRECTION('',(0.,-1.,1.48029736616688E-13));
#622=DIRECTION('',(0.,-1.48029736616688E-13,-1.));
#623=AXIS2_PLACEMENT_3D('',#620,#621,#622);
#624=PLANE('',#623);
#625=DIRECTION('',(0.,-1.48029736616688E-13,-1.));
#626=VECTOR('',#625,1.);
#627=CARTESIAN_POINT('',(1152.45,2100.,13.3700000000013));
#628=LINE('',#627,#626);
#629=CARTESIAN_POINT('',(1152.45,2100.,13.3700000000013));
#630=VERTEX_POINT('',#629);
#631=EDGE_CURVE('E654',#630,#599,#628,.T.);
#632=ORIENTED_EDGE('',*,*,#631,.F.);
#633=DIRECTION('',(-1.,0.,0.));
#634=VECTOR('',#633,1.);
#635=CARTESIAN_POINT('',(1170.95,2100.,13.3700000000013));
#636=LINE('',#635,#634);
#637=CARTESIAN_POINT('',(1164.45,2100.,13.3700000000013));
#638=VERTEX_POINT('',#637);
#639=EDGE_CURVE('E586',#638,#630,#636,.T.);
#640=ORIENTED_EDGE('',*,*,#639,.F.);
#641=DIRECTION('',(0.,1.48029736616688E-13,1.));
#642=VECTOR('',#641,1.);
#643=CARTESIAN_POINT('',(1164.45,2100.,13.3700000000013));
#644=LINE('',#643,#642);
#645=EDGE_CURVE('E640',#607,#638,#644,.T.);
#646=ORIENTED_EDGE('',*,*,#645,.F.);
#647=ORIENTED_EDGE('',*,*,#608,.T.);
#648=EDGE_LOOP('',(#632,#640,#646,#647));
#649=FACE_BOUND('',#648,.T.);
#650=ADVANCED_FACE('F703',(#649),#624,.F.);
#651=CARTESIAN_POINT('',(1170.95,2090.,13.3700000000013));
#652=DIRECTION('',(0.,0.,-1.));
#653=DIRECTION('',(0.,1.,0.));
#654=AXIS2_PLACEMENT_3D('',#651,#652,#653);
#655=PLANE('',#654);
#656=ORIENTED_EDGE('',*,*,#639,.T.);
#657=DIRECTION('',(0.,-1.,0.));
#658=VECTOR('',#657,1.);
#659=CARTESIAN_POINT('',(1152.45,7813.97164808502,13.3700000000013));
#660=LINE('',#659,#658);
#661=CARTESIAN_POINT('',(1152.45,2090.,13.3700000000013));
#662=VERTEX_POINT('',#661);
#663=EDGE_CURVE('E617',#630,#662,#660,.T.);
#664=ORIENTED_EDGE('',*,*,#663,.T.);
#665=DIRECTION('',(-1.,0.,0.));
#666=VECTOR('',#665,1.);
#667=CARTESIAN_POINT('',(1170.95,2090.,13.3700000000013));
#668=LINE('',#667,#666);
#669=CARTESIAN_POINT('',(1164.45,2090.,13.3700000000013));
#670=VERTEX_POINT('',#669);
#671=EDGE_CURVE('E583',#670,#662,#668,.T.);
#672=ORIENTED_EDGE('',*,*,#671,.F.);
#673=DIRECTION('',(0.,-1.,0.));
#674=VECTOR('',#673,1.);
#675=CARTESIAN_POINT('',(1164.45,7813.97164808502,13.3700000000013));
#676=LINE('',#675,#674);
#677=EDGE_CURVE('E627',#638,#670,#676,.T.);
#678=ORIENTED_EDGE('',*,*,#677,.F.);
#679=EDGE_LOOP('',(#656,#664,#672,#678));
#680=FACE_BOUND('',#679,.T.);
#681=ADVANCED_FACE('F625',(#680),#655,.F.);
#682=CARTESIAN_POINT('',(1170.95,2090.,-3.40000000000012));
#683=DIRECTION('',(0.,1.,0.));
#684=DIRECTION('',(0.,0.,1.));
#685=AXIS2_PLACEMENT_3D('',#682,#683,#684);
#686=PLANE('',#685);
#687=DIRECTION('',(0.906307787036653,0.,0.422618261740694));
#688=VECTOR('',#687,1.);
#689=CARTESIAN_POINT('',(1164.95275623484,2090.,9.46113075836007));
#690=LINE('',#689,#688);
#691=CARTESIAN_POINT('',(1152.45,2090.,3.6309997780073));
#692=VERTEX_POINT('',#691);
#693=EDGE_CURVE('E642',#473,#692,#690,.T.);
#694=ORIENTED_EDGE('',*,*,#693,.F.);
#695=ORIENTED_EDGE('',*,*,#474,.T.);
#696=DIRECTION('',(-1.,0.,0.));
#697=VECTOR('',#696,1.);
#698=CARTESIAN_POINT('',(1170.95,2090.,-3.40000000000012));
#699=LINE('',#698,#697);
#700=EDGE_CURVE('E580',#345,#465,#699,.T.);
#701=ORIENTED_EDGE('',*,*,#700,.F.);
#702=ORIENTED_EDGE('',*,*,#346,.F.);
#703=DIRECTION('',(0.906307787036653,0.,-0.422618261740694));
#704=VECTOR('',#703,1.);
#705=CARTESIAN_POINT('',(1172.48208888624,2090.,-0.114424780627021));
#706=LINE('',#705,#704);
#707=CARTESIAN_POINT('',(1164.45,2090.,3.6309997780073));
#708=VERTEX_POINT('',#707);
#709=EDGE_CURVE('E632',#708,#337,#706,.T.);
#710=ORIENTED_EDGE('',*,*,#709,.F.);
#711=DIRECTION('',(0.,0.,-1.));
#712=VECTOR('',#711,1.);
#713=CARTESIAN_POINT('',(1164.45,2090.,-3.40000000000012));
#714=LINE('',#713,#712);
#715=EDGE_CURVE('E606',#670,#708,#714,.T.);
#716=ORIENTED_EDGE('',*,*,#715,.F.);
#717=ORIENTED_EDGE('',*,*,#671,.T.);
#718=DIRECTION('',(0.,0.,1.));
#719=VECTOR('',#718,1.);
#720=CARTESIAN_POINT('',(1152.45,2090.,-3.40000000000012));
#721=LINE('',#720,#719);
#722=EDGE_CURVE('E326',#692,#662,#721,.T.);
#723=ORIENTED_EDGE('',*,*,#722,.F.);
#724=EDGE_LOOP('',(#694,#695,#701,#702,#710,#716,#717,#723));
#725=FACE_BOUND('',#724,.T.);
#726=ADVANCED_FACE('F629',(#725),#686,.F.);
#727=CARTESIAN_POINT('',(1170.95,2120.,-19.4000000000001));
#728=DIRECTION('',(0.,0.,1.));
#729=DIRECTION('',(0.,-1.,0.));
#730=AXIS2_PLACEMENT_3D('',#727,#728,#729);
#731=PLANE('',#730);
#732=ORIENTED_EDGE('',*,*,#434,.T.);
#733=ORIENTED_EDGE('',*,*,#531,.T.);
#734=ORIENTED_EDGE('',*,*,#386,.F.);
#735=DIRECTION('',(-1.,0.,0.));
#736=VECTOR('',#735,1.);
#737=CARTESIAN_POINT('',(1170.95,2090.,-19.4000000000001));
#738=LINE('',#737,#736);
#739=EDGE_CURVE('E543',#377,#433,#738,.T.);
#740=ORIENTED_EDGE('',*,*,#739,.T.);
#741=EDGE_LOOP('',(#732,#733,#734,#740));
#742=FACE_BOUND('',#741,.T.);
#743=ADVANCED_FACE('F320',(#742),#731,.F.);
#744=CARTESIAN_POINT('',(1170.95,2094.,0.599999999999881));
#745=DIRECTION('',(0.,0.,-1.));
#746=DIRECTION('',(0.,1.,0.));
#747=AXIS2_PLACEMENT_3D('',#744,#745,#746);
#748=PLANE('',#747);
#749=ORIENTED_EDGE('',*,*,#488,.T.);
#750=ORIENTED_EDGE('',*,*,#584,.F.);
#751=ORIENTED_EDGE('',*,*,#330,.F.);
#752=ORIENTED_EDGE('',*,*,#509,.T.);
#753=EDGE_LOOP('',(#749,#750,#751,#752));
#754=FACE_BOUND('',#753,.T.);
#755=ADVANCED_FACE('F707',(#754),#748,.F.);
#756=CARTESIAN_POINT('',(1170.95,2100.,-3.40000000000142));
#757=DIRECTION('',(0.,1.30407837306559E-13,1.));
#758=DIRECTION('',(0.,-1.,1.30407837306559E-13));
#759=AXIS2_PLACEMENT_3D('',#756,#757,#758);
#760=PLANE('',#759);
#761=ORIENTED_EDGE('',*,*,#466,.T.);
#762=DIRECTION('',(-1.,0.,0.));
#763=VECTOR('',#762,1.);
#764=CARTESIAN_POINT('',(1170.95,2100.,-3.40000000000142));
#765=LINE('',#764,#763);
#766=EDGE_CURVE('E577',#353,#457,#765,.T.);
#767=ORIENTED_EDGE('',*,*,#766,.F.);
#768=ORIENTED_EDGE('',*,*,#354,.F.);
#769=ORIENTED_EDGE('',*,*,#700,.T.);
#770=EDGE_LOOP('',(#761,#767,#768,#769));
#771=FACE_BOUND('',#770,.T.);
#772=ADVANCED_FACE('F685',(#771),#760,.F.);
#773=CARTESIAN_POINT('',(1170.95,2100.,-11.4000000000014));
#774=DIRECTION('',(0.,1.,0.));
#775=DIRECTION('',(0.,0.,1.));
#776=AXIS2_PLACEMENT_3D('',#773,#774,#775);
#777=PLANE('',#776);
#778=ORIENTED_EDGE('',*,*,#458,.T.);
#779=DIRECTION('',(-1.,0.,0.));
#780=VECTOR('',#779,1.);
#781=CARTESIAN_POINT('',(1170.95,2100.,-11.4000000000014));
#782=LINE('',#781,#780);
#783=EDGE_CURVE('E574',#361,#449,#782,.T.);
#784=ORIENTED_EDGE('',*,*,#783,.F.);
#785=ORIENTED_EDGE('',*,*,#362,.F.);
#786=ORIENTED_EDGE('',*,*,#766,.T.);
#787=EDGE_LOOP('',(#778,#784,#785,#786));
#788=FACE_BOUND('',#787,.T.);
#789=ADVANCED_FACE('F681',(#788),#777,.F.);
#790=CARTESIAN_POINT('',(1170.95,2090.,-11.4000000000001));
#791=DIRECTION('',(0.,-1.30451205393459E-13,-1.));
#792=DIRECTION('',(0.,1.,-1.30451205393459E-13));
#793=AXIS2_PLACEMENT_3D('',#790,#791,#792);
#794=PLANE('',#793);
#795=ORIENTED_EDGE('',*,*,#450,.T.);
#796=DIRECTION('',(-1.,0.,0.));
#797=VECTOR('',#796,1.);
#798=CARTESIAN_POINT('',(1170.95,2090.,-11.4000000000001));
#799=LINE('',#798,#797);
#800=EDGE_CURVE('E571',#369,#441,#799,.T.);
#801=ORIENTED_EDGE('',*,*,#800,.F.);
#802=ORIENTED_EDGE('',*,*,#370,.F.);
#803=ORIENTED_EDGE('',*,*,#783,.T.);
#804=EDGE_LOOP('',(#795,#801,#802,#803));
#805=FACE_BOUND('',#804,.T.);
#806=ADVANCED_FACE('F677',(#805),#794,.F.);
#807=CARTESIAN_POINT('',(1170.95,2090.,-19.4000000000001));
#808=DIRECTION('',(0.,1.,0.));
#809=DIRECTION('',(0.,0.,1.));
#810=AXIS2_PLACEMENT_3D('',#807,#808,#809);
#811=PLANE('',#810);
#812=ORIENTED_EDGE('',*,*,#442,.T.);
#813=ORIENTED_EDGE('',*,*,#739,.F.);
#814=ORIENTED_EDGE('',*,*,#378,.F.);
#815=ORIENTED_EDGE('',*,*,#800,.T.);
#816=EDGE_LOOP('',(#812,#813,#814,#815));
#817=FACE_BOUND('',#816,.T.);
#818=ADVANCED_FACE('F672',(#817),#811,.F.);
#819=CARTESIAN_POINT('',(1145.95,7813.97164808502,0.599999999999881));
#820=DIRECTION('',(-0.422618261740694,0.,0.906307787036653));
#821=DIRECTION('',(0.906307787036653,0.,0.422618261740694));
#822=AXIS2_PLACEMENT_3D('',#819,#820,#821);
#823=PLANE('',#822);
#824=DIRECTION('',(0.,-1.,0.));
#825=VECTOR('',#824,1.);
#826=CARTESIAN_POINT('',(1152.45,7813.97164808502,3.6309997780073));
#827=LINE('',#826,#825);
#828=EDGE_CURVE('E620',#547,#692,#827,.T.);
#829=ORIENTED_EDGE('',*,*,#828,.F.);
#830=ORIENTED_EDGE('',*,*,#548,.T.);
#831=ORIENTED_EDGE('',*,*,#482,.F.);
#832=ORIENTED_EDGE('',*,*,#693,.T.);
#833=EDGE_LOOP('',(#829,#830,#831,#832));
#834=FACE_BOUND('',#833,.T.);
#835=ADVANCED_FACE('F704',(#834),#823,.T.);
#836=CARTESIAN_POINT('',(1152.45,7813.97164808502,3.6309997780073));
#837=DIRECTION('',(-1.,0.,0.));
#838=DIRECTION('',(0.,0.,1.));
#839=AXIS2_PLACEMENT_3D('',#836,#837,#838);
#840=PLANE('',#839);
#841=ORIENTED_EDGE('',*,*,#600,.T.);
#842=ORIENTED_EDGE('',*,*,#556,.T.);
#843=ORIENTED_EDGE('',*,*,#828,.T.);
#844=ORIENTED_EDGE('',*,*,#722,.T.);
#845=ORIENTED_EDGE('',*,*,#663,.F.);
#846=ORIENTED_EDGE('',*,*,#631,.T.);
#847=EDGE_LOOP('',(#841,#842,#843,#844,#845,#846));
#848=FACE_BOUND('',#847,.T.);
#849=ADVANCED_FACE('F616',(#848),#840,.T.);
#850=CARTESIAN_POINT('',(1164.45,7813.97164808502,3.6309997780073));
#851=DIRECTION('',(1.,0.,0.));
#852=DIRECTION('',(0.,0.,-1.));
#853=AXIS2_PLACEMENT_3D('',#850,#851,#852);
#854=PLANE('',#853);
#855=DIRECTION('',(0.,-1.,0.));
#856=VECTOR('',#855,1.);
#857=CARTESIAN_POINT('',(1164.45,7813.97164808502,3.6309997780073));
#858=LINE('',#857,#856);
#859=EDGE_CURVE('E513',#571,#708,#858,.T.);
#860=ORIENTED_EDGE('',*,*,#859,.F.);
#861=ORIENTED_EDGE('',*,*,#572,.T.);
#862=ORIENTED_EDGE('',*,*,#614,.T.);
#863=ORIENTED_EDGE('',*,*,#645,.T.);
#864=ORIENTED_EDGE('',*,*,#677,.T.);
#865=ORIENTED_EDGE('',*,*,#715,.T.);
#866=EDGE_LOOP('',(#860,#861,#862,#863,#864,#865));
#867=FACE_BOUND('',#866,.T.);
#868=ADVANCED_FACE('F692',(#867),#854,.T.);
#869=CARTESIAN_POINT('',(1170.95,7813.97164808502,0.599999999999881));
#870=DIRECTION('',(0.422618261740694,0.,0.906307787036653));
#871=DIRECTION('',(0.906307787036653,0.,-0.422618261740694));
#872=AXIS2_PLACEMENT_3D('',#869,#870,#871);
#873=PLANE('',#872);
#874=ORIENTED_EDGE('',*,*,#338,.T.);
#875=ORIENTED_EDGE('',*,*,#578,.T.);
#876=ORIENTED_EDGE('',*,*,#859,.T.);
#877=ORIENTED_EDGE('',*,*,#709,.T.);
#878=EDGE_LOOP('',(#874,#875,#876,#877));
#879=FACE_BOUND('',#878,.T.);
#880=ADVANCED_FACE('F690',(#879),#873,.T.);
#881=CARTESIAN_POINT('',(1143.44999999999,2103.,-850.03));
#882=DIRECTION('',(0.,0.,-1.));
#883=DIRECTION('',(-1.,0.,0.));
#884=AXIS2_PLACEMENT_3D('',#881,#882,#883);
#885=PLANE('',#884);
#886=DIRECTION('',(0.,1.,0.));
#887=VECTOR('',#886,1.);
#888=CARTESIAN_POINT('',(1143.44999999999,2125.,-850.03));
#889=LINE('',#888,#887);
#890=CARTESIAN_POINT('',(1143.44999999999,2103.,-850.03));
#891=VERTEX_POINT('',#890);
#892=CARTESIAN_POINT('',(1143.44999999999,2125.,-850.03));
#893=VERTEX_POINT('',#892);
#894=EDGE_CURVE('E481',#891,#893,#889,.T.);
#895=ORIENTED_EDGE('',*,*,#894,.F.);
#896=DIRECTION('',(-1.,0.,0.));
#897=VECTOR('',#896,1.);
#898=CARTESIAN_POINT('',(1173.44999999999,2103.,-850.03));
#899=LINE('',#898,#897);
#900=CARTESIAN_POINT('',(1173.44999999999,2103.,-850.03));
#901=VERTEX_POINT('',#900);
#902=EDGE_CURVE('E473',#901,#891,#899,.T.);
#903=ORIENTED_EDGE('',*,*,#902,.F.);
#904=DIRECTION('',(0.,-1.,0.));
#905=VECTOR('',#904,1.);
#906=CARTESIAN_POINT('',(1173.44999999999,2125.,-850.03));
#907=LINE('',#906,#905);
#908=CARTESIAN_POINT('',(1173.44999999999,2125.,-850.03));
#909=VERTEX_POINT('',#908);
#910=EDGE_CURVE('E484',#909,#901,#907,.T.);
#911=ORIENTED_EDGE('',*,*,#910,.F.);
#912=DIRECTION('',(1.,0.,0.));
#913=VECTOR('',#912,1.);
#914=CARTESIAN_POINT('',(1173.44999999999,2125.,-850.03));
#915=LINE('',#914,#913);
#916=EDGE_CURVE('E465',#893,#909,#915,.T.);
#917=ORIENTED_EDGE('',*,*,#916,.F.);
#918=EDGE_LOOP('',(#895,#903,#911,#917));
#919=FACE_BOUND('',#918,.T.);
#920=ORIENTED_EDGE('',*,*,#418,.F.);
#921=ORIENTED_EDGE('',*,*,#502,.T.);
#922=ORIENTED_EDGE('',*,*,#314,.T.);
#923=ORIENTED_EDGE('',*,*,#524,.T.);
#924=EDGE_LOOP('',(#920,#921,#922,#923));
#925=FACE_BOUND('',#924,.T.);
#926=ADVANCED_FACE('F478',(#919,#925),#885,.F.);
#927=CARTESIAN_POINT('',(1143.44999999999,2125.,-850.03));
#928=DIRECTION('',(-1.,0.,0.));
#929=DIRECTION('',(0.,0.,1.));
#930=AXIS2_PLACEMENT_3D('',#927,#928,#929);
#931=PLANE('',#930);
#932=DIRECTION('',(0.,1.,0.));
#933=VECTOR('',#932,1.);
#934=CARTESIAN_POINT('',(1143.44999999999,2125.,-881.03));
#935=LINE('',#934,#933);
#936=CARTESIAN_POINT('',(1143.44999999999,2103.,-881.03));
#937=VERTEX_POINT('',#936);
#938=CARTESIAN_POINT('',(1143.44999999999,2125.,-881.03));
#939=VERTEX_POINT('',#938);
#940=EDGE_CURVE('E496',#937,#939,#935,.T.);
#941=ORIENTED_EDGE('',*,*,#940,.F.);
#942=DIRECTION('',(0.,0.,-1.));
#943=VECTOR('',#942,1.);
#944=CARTESIAN_POINT('',(1143.44999999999,2103.,-850.03));
#945=LINE('',#944,#943);
#946=EDGE_CURVE('E487',#891,#937,#945,.T.);
#947=ORIENTED_EDGE('',*,*,#946,.F.);
#948=ORIENTED_EDGE('',*,*,#894,.T.);
#949=DIRECTION('',(0.,0.,-1.));
#950=VECTOR('',#949,1.);
#951=CARTESIAN_POINT('',(1143.44999999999,2125.,-850.03));
#952=LINE('',#951,#950);
#953=EDGE_CURVE('E462',#893,#939,#952,.T.);
#954=ORIENTED_EDGE('',*,*,#953,.T.);
#955=EDGE_LOOP('',(#941,#947,#948,#954));
#956=FACE_BOUND('',#955,.T.);
#957=ADVANCED_FACE('F486',(#956),#931,.T.);
#958=CARTESIAN_POINT('',(1173.44999999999,2103.,-850.03));
#959=DIRECTION('',(0.,-1.,0.));
#960=DIRECTION('',(0.,0.,-1.));
#961=AXIS2_PLACEMENT_3D('',#958,#959,#960);
#962=PLANE('',#961);
#963=DIRECTION('',(-1.,0.,0.));
#964=VECTOR('',#963,1.);
#965=CARTESIAN_POINT('',(1173.44999999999,2103.,-881.03));
#966=LINE('',#965,#964);
#967=CARTESIAN_POINT('',(1173.44999999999,2103.,-881.03));
#968=VERTEX_POINT('',#967);
#969=EDGE_CURVE('E488',#968,#937,#966,.T.);
#970=ORIENTED_EDGE('',*,*,#969,.F.);
#971=DIRECTION('',(0.,0.,-1.));
#972=VECTOR('',#971,1.);
#973=CARTESIAN_POINT('',(1173.44999999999,2103.,-850.03));
#974=LINE('',#973,#972);
#975=EDGE_CURVE('E503',#901,#968,#974,.T.);
#976=ORIENTED_EDGE('',*,*,#975,.F.);
#977=ORIENTED_EDGE('',*,*,#902,.T.);
#978=ORIENTED_EDGE('',*,*,#946,.T.);
#979=EDGE_LOOP('',(#970,#976,#977,#978));
#980=FACE_BOUND('',#979,.T.);
#981=ADVANCED_FACE('F716',(#980),#962,.T.);
#982=CARTESIAN_POINT('',(1173.44999999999,2125.,-850.03));
#983=DIRECTION('',(1.,0.,0.));
#984=DIRECTION('',(0.,0.,-1.));
#985=AXIS2_PLACEMENT_3D('',#982,#983,#984);
#986=PLANE('',#985);
#987=DIRECTION('',(0.,-1.,0.));
#988=VECTOR('',#987,1.);
#989=CARTESIAN_POINT('',(1173.44999999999,2125.,-881.03));
#990=LINE('',#989,#988);
#991=CARTESIAN_POINT('',(1173.44999999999,2125.,-881.03));
#992=VERTEX_POINT('',#991);
#993=EDGE_CURVE('E491',#992,#968,#990,.T.);
#994=ORIENTED_EDGE('',*,*,#993,.F.);
#995=DIRECTION('',(0.,0.,-1.));
#996=VECTOR('',#995,1.);
#997=CARTESIAN_POINT('',(1173.44999999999,2125.,-850.03));
#998=LINE('',#997,#996);
#999=EDGE_CURVE('E472',#909,#992,#998,.T.);
#1000=ORIENTED_EDGE('',*,*,#999,.F.);
#1001=ORIENTED_EDGE('',*,*,#910,.T.);
#1002=ORIENTED_EDGE('',*,*,#975,.T.);
#1003=EDGE_LOOP('',(#994,#1000,#1001,#1002));
#1004=FACE_BOUND('',#1003,.T.);
#1005=ADVANCED_FACE('F884',(#1004),#986,.T.);
#1006=CARTESIAN_POINT('',(1173.44999999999,2125.,-850.03));
#1007=DIRECTION('',(0.,1.,0.));
#1008=DIRECTION('',(0.,0.,1.));
#1009=AXIS2_PLACEMENT_3D('',#1006,#1007,#1008);
#1010=PLANE('',#1009);
#1011=DIRECTION('',(1.,0.,0.));
#1012=VECTOR('',#1011,1.);
#1013=CARTESIAN_POINT('',(1173.44999999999,2125.,-881.03));
#1014=LINE('',#1013,#1012);
#1015=EDGE_CURVE('E467',#939,#992,#1014,.T.);
#1016=ORIENTED_EDGE('',*,*,#1015,.F.);
#1017=ORIENTED_EDGE('',*,*,#953,.F.);
#1018=ORIENTED_EDGE('',*,*,#916,.T.);
#1019=ORIENTED_EDGE('',*,*,#999,.T.);
#1020=EDGE_LOOP('',(#1016,#1017,#1018,#1019));
#1021=FACE_BOUND('',#1020,.T.);
#1022=ADVANCED_FACE('F464',(#1021),#1010,.T.);
#1023=CARTESIAN_POINT('',(1145.95,2105.,-881.03));
#1024=DIRECTION('',(0.,0.,-1.));
#1025=DIRECTION('',(-1.,0.,0.));
#1026=AXIS2_PLACEMENT_3D('',#1023,#1024,#1025);
#1027=PLANE('',#1026);
#1028=ORIENTED_EDGE('',*,*,#940,.T.);
#1029=ORIENTED_EDGE('',*,*,#1015,.T.);
#1030=ORIENTED_EDGE('',*,*,#993,.T.);
#1031=ORIENTED_EDGE('',*,*,#969,.T.);
#1032=EDGE_LOOP('',(#1028,#1029,#1030,#1031));
#1033=FACE_BOUND('',#1032,.T.);
#1034=ADVANCED_FACE('F757',(#1033),#1027,.T.);
#1035=CLOSED_SHELL('',(#396,#492,#514,#536,#588,#619,#650,#681,#726,#743,#755,#772,#789,#806,
#818,#835,#849,#868,#880,#926,#957,#981,#1005,#1022,#1034));
#1036=MANIFOLD_SOLID_BREP('B6',#1035);
#1037=CARTESIAN_POINT('',(1175.95,22.,-11.4000000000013));
#1038=DIRECTION('',(0.,0.,-1.));
#1039=DIRECTION('',(0.,1.,0.));
#1040=AXIS2_PLACEMENT_3D('',#1037,#1038,#1039);
#1041=PLANE('',#1040);
#1042=DIRECTION('',(0.,-1.,0.));
#1043=VECTOR('',#1042,1.);
#1044=CARTESIAN_POINT('',(1140.95,22.,-11.4000000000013));
#1045=LINE('',#1044,#1043);
#1046=CARTESIAN_POINT('',(1140.95,22.,-11.4000000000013));
#1047=VERTEX_POINT('',#1046);
#1048=CARTESIAN_POINT('',(1140.95,0.,-11.4));
#1049=VERTEX_POINT('',#1048);
#1050=EDGE_CURVE('E1037',#1047,#1049,#1045,.T.);
#1051=ORIENTED_EDGE('',*,*,#1050,.T.);
#1052=DIRECTION('',(-1.,0.,0.));
#1053=VECTOR('',#1052,1.);
#1054=CARTESIAN_POINT('',(1175.95,0.,-11.4));
#1055=LINE('',#1054,#1053);
#1056=CARTESIAN_POINT('',(1175.95,0.,-11.4));
#1057=VERTEX_POINT('',#1056);
#1058=EDGE_CURVE('E316',#1057,#1049,#1055,.T.);
#1059=ORIENTED_EDGE('',*,*,#1058,.F.);
#1060=DIRECTION('',(0.,-1.,0.));
#1061=VECTOR('',#1060,1.);
#1062=CARTESIAN_POINT('',(1175.95,22.,-11.4000000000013));
#1063=LINE('',#1062,#1061);
#1064=CARTESIAN_POINT('',(1175.95,22.,-11.4000000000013));
#1065=VERTEX_POINT('',#1064);
#1066=EDGE_CURVE('E1051',#1065,#1057,#1063,.T.);
#1067=ORIENTED_EDGE('',*,*,#1066,.F.);
#1068=DIRECTION('',(-1.,0.,0.));
#1069=VECTOR('',#1068,1.);
#1070=CARTESIAN_POINT('',(1175.95,22.,-11.4000000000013));
#1071=LINE('',#1070,#1069);
#1072=EDGE_CURVE('E1033',#1065,#1047,#1071,.T.);
#1073=ORIENTED_EDGE('',*,*,#1072,.T.);
#1074=EDGE_LOOP('',(#1051,#1059,#1067,#1073));
#1075=FACE_BOUND('',#1074,.T.);
#1076=ADVANCED_FACE('F941',(#1075),#1041,.F.);
#1077=CARTESIAN_POINT('',(1175.95,0.,-11.4));
#1078=DIRECTION('',(0.,-1.,0.));
#1079=DIRECTION('',(0.,0.,-1.));
#1080=AXIS2_PLACEMENT_3D('',#1077,#1078,#1079);
#1081=PLANE('',#1080);
#1082=DIRECTION('',(0.,0.,1.));
#1083=VECTOR('',#1082,1.);
#1084=CARTESIAN_POINT('',(1140.95,0.,-11.4));
#1085=LINE('',#1084,#1083);
#1086=CARTESIAN_POINT('',(1140.95,0.,-3.4));
#1087=VERTEX_POINT('',#1086);
#1088=EDGE_CURVE('E1040',#1049,#1087,#1085,.T.);
#1089=ORIENTED_EDGE('',*,*,#1088,.T.);
#1090=DIRECTION('',(-1.,0.,0.));
#1091=VECTOR('',#1090,1.);
#1092=CARTESIAN_POINT('',(1175.95,0.,-3.4));
#1093=LINE('',#1092,#1091);
#1094=CARTESIAN_POINT('',(1175.95,0.,-3.4));
#1095=VERTEX_POINT('',#1094);
#1096=EDGE_CURVE('E949',#1095,#1087,#1093,.T.);
#1097=ORIENTED_EDGE('',*,*,#1096,.F.);
#1098=DIRECTION('',(0.,0.,1.));
#1099=VECTOR('',#1098,1.);
#1100=CARTESIAN_POINT('',(1175.95,0.,-11.4));
#1101=LINE('',#1100,#1099);
#1102=EDGE_CURVE('E1000',#1057,#1095,#1101,.T.);
#1103=ORIENTED_EDGE('',*,*,#1102,.F.);
#1104=ORIENTED_EDGE('',*,*,#1058,.T.);
#1105=EDGE_LOOP('',(#1089,#1097,#1103,#1104));
#1106=FACE_BOUND('',#1105,.T.);
#1107=ADVANCED_FACE('F1086',(#1106),#1081,.F.);
#1108=CARTESIAN_POINT('',(1175.95,0.,-3.4));
#1109=DIRECTION('',(0.,0.,1.));
#1110=DIRECTION('',(0.,-1.,0.));
#1111=AXIS2_PLACEMENT_3D('',#1108,#1109,#1110);
#1112=PLANE('',#1111);
#1113=DIRECTION('',(0.,1.,0.));
#1114=VECTOR('',#1113,1.);
#1115=CARTESIAN_POINT('',(1140.95,0.,-3.4));
#1116=LINE('',#1115,#1114);
#1117=CARTESIAN_POINT('',(1140.95,21.9999999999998,-3.4000000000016));
#1118=VERTEX_POINT('',#1117);
#1119=EDGE_CURVE('E1042',#1087,#1118,#1116,.T.);
#1120=ORIENTED_EDGE('',*,*,#1119,.T.);
#1121=DIRECTION('',(-1.,0.,0.));
#1122=VECTOR('',#1121,1.);
#1123=CARTESIAN_POINT('',(1175.95,21.9999999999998,-3.4000000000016));
#1124=LINE('',#1123,#1122);
#1125=CARTESIAN_POINT('',(1175.95,21.9999999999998,-3.4000000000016));
#1126=VERTEX_POINT('',#1125);
#1127=EDGE_CURVE('E1058',#1126,#1118,#1124,.T.);
#1128=ORIENTED_EDGE('',*,*,#1127,.F.);
#1129=DIRECTION('',(0.,1.,0.));
#1130=VECTOR('',#1129,1.);
#1131=CARTESIAN_POINT('',(1175.95,0.,-3.4));
#1132=LINE('',#1131,#1130);
#1133=EDGE_CURVE('E1066',#1095,#1126,#1132,.T.);
#1134=ORIENTED_EDGE('',*,*,#1133,.F.);
#1135=ORIENTED_EDGE('',*,*,#1096,.T.);
#1136=EDGE_LOOP('',(#1120,#1128,#1134,#1135));
#1137=FACE_BOUND('',#1136,.T.);
#1138=ADVANCED_FACE('F1064',(#1137),#1112,.F.);
#1139=CARTESIAN_POINT('',(1175.95,22.,0.349999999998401));
#1140=DIRECTION('',(0.,-1.,0.));
#1141=DIRECTION('',(0.,0.,-1.));
#1142=AXIS2_PLACEMENT_3D('',#1139,#1140,#1141);
#1143=PLANE('',#1142);
#1144=DIRECTION('',(0.,0.,1.));
#1145=VECTOR('',#1144,1.);
#1146=CARTESIAN_POINT('',(1140.95,22.,0.349999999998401));
#1147=LINE('',#1146,#1145);
#1148=CARTESIAN_POINT('',(1140.95,22.,0.349999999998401));
#1149=VERTEX_POINT('',#1148);
#1150=EDGE_CURVE('E1044',#1118,#1149,#1147,.T.);
#1151=ORIENTED_EDGE('',*,*,#1150,.T.);
#1152=DIRECTION('',(-1.,0.,0.));
#1153=VECTOR('',#1152,1.);
#1154=CARTESIAN_POINT('',(1175.95,22.,0.349999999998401));
#1155=LINE('',#1154,#1153);
#1156=CARTESIAN_POINT('',(1175.95,22.,0.349999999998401));
#1157=VERTEX_POINT('',#1156);
#1158=EDGE_CURVE('E1055',#1157,#1149,#1155,.T.);
#1159=ORIENTED_EDGE('',*,*,#1158,.F.);
#1160=DIRECTION('',(0.,0.,1.));
#1161=VECTOR('',#1160,1.);
#1162=CARTESIAN_POINT('',(1175.95,22.,0.349999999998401));
#1163=LINE('',#1162,#1161);
#1164=EDGE_CURVE('E1078',#1126,#1157,#1163,.T.);
#1165=ORIENTED_EDGE('',*,*,#1164,.F.);
#1166=ORIENTED_EDGE('',*,*,#1127,.T.);
#1167=EDGE_LOOP('',(#1151,#1159,#1165,#1166));
#1168=FACE_BOUND('',#1167,.T.);
#1169=ADVANCED_FACE('F1074',(#1168),#1143,.F.);
#1170=CARTESIAN_POINT('',(1175.95,-3.,0.349999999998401));
#1171=DIRECTION('',(0.,0.,-1.));
#1172=DIRECTION('',(-1.,0.,0.));
#1173=AXIS2_PLACEMENT_3D('',#1170,#1171,#1172);
#1174=PLANE('',#1173);
#1175=DIRECTION('',(0.,-1.,0.));
#1176=VECTOR('',#1175,1.);
#1177=CARTESIAN_POINT('',(1140.95,-3.,0.349999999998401));
#1178=LINE('',#1177,#1176);
#1179=CARTESIAN_POINT('',(1140.95,-3.,0.349999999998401));
#1180=VERTEX_POINT('',#1179);
#1181=EDGE_CURVE('E1046',#1149,#1180,#1178,.T.);
#1182=ORIENTED_EDGE('',*,*,#1181,.T.);
#1183=DIRECTION('',(-1.,0.,0.));
#1184=VECTOR('',#1183,1.);
#1185=CARTESIAN_POINT('',(1175.95,-3.,0.349999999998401));
#1186=LINE('',#1185,#1184);
#1187=CARTESIAN_POINT('',(1175.95,-3.,0.349999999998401));
#1188=VERTEX_POINT('',#1187);
#1189=EDGE_CURVE('E1028',#1188,#1180,#1186,.T.);
#1190=ORIENTED_EDGE('',*,*,#1189,.F.);
#1191=DIRECTION('',(0.,-1.,0.));
#1192=VECTOR('',#1191,1.);
#1193=CARTESIAN_POINT('',(1175.95,-3.,0.349999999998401));
#1194=LINE('',#1193,#1192);
#1195=EDGE_CURVE('E1019',#1157,#1188,#1194,.T.);
#1196=ORIENTED_EDGE('',*,*,#1195,.F.);
#1197=ORIENTED_EDGE('',*,*,#1158,.T.);
#1198=EDGE_LOOP('',(#1182,#1190,#1196,#1197));
#1199=FACE_BOUND('',#1198,.T.);
#1200=ADVANCED_FACE('F1077',(#1199),#1174,.F.);
#1201=CARTESIAN_POINT('',(1175.95,-3.,-15.7500000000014));
#1202=DIRECTION('',(0.,1.,0.));
#1203=DIRECTION('',(0.,0.,1.));
#1204=AXIS2_PLACEMENT_3D('',#1201,#1202,#1203);
#1205=PLANE('',#1204);
#1206=DIRECTION('',(0.,0.,-1.));
#1207=VECTOR('',#1206,1.);
#1208=CARTESIAN_POINT('',(1140.95,-3.,-15.7500000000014));
#1209=LINE('',#1208,#1207);
#1210=CARTESIAN_POINT('',(1140.95,-3.,-15.7500000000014));
#1211=VERTEX_POINT('',#1210);
#1212=EDGE_CURVE('E1027',#1180,#1211,#1209,.T.);
#1213=ORIENTED_EDGE('',*,*,#1212,.T.);
#1214=DIRECTION('',(-1.,0.,0.));
#1215=VECTOR('',#1214,1.);
#1216=CARTESIAN_POINT('',(1175.95,-3.,-15.7500000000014));
#1217=LINE('',#1216,#1215);
#1218=CARTESIAN_POINT('',(1175.95,-3.,-15.7500000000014));
#1219=VERTEX_POINT('',#1218);
#1220=EDGE_CURVE('E1024',#1219,#1211,#1217,.T.);
#1221=ORIENTED_EDGE('',*,*,#1220,.F.);
#1222=DIRECTION('',(0.,0.,-1.));
#1223=VECTOR('',#1222,1.);
#1224=CARTESIAN_POINT('',(1175.95,-3.,-15.7500000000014));
#1225=LINE('',#1224,#1223);
#1226=EDGE_CURVE('E1013',#1188,#1219,#1225,.T.);
#1227=ORIENTED_EDGE('',*,*,#1226,.F.);
#1228=ORIENTED_EDGE('',*,*,#1189,.T.);
#1229=EDGE_LOOP('',(#1213,#1221,#1227,#1228));
#1230=FACE_BOUND('',#1229,.T.);
#1231=ADVANCED_FACE('F1025',(#1230),#1205,.F.);
#1232=CARTESIAN_POINT('',(1175.95,22.,-15.7500000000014));
#1233=DIRECTION('',(0.,0.,1.));
#1234=DIRECTION('',(0.,-1.,0.));
#1235=AXIS2_PLACEMENT_3D('',#1232,#1233,#1234);
#1236=PLANE('',#1235);
#1237=DIRECTION('',(0.,1.,0.));
#1238=VECTOR('',#1237,1.);
#1239=CARTESIAN_POINT('',(1140.95,22.,-15.7500000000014));
#1240=LINE('',#1239,#1238);
#1241=CARTESIAN_POINT('',(1140.95,22.,-15.7500000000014));
#1242=VERTEX_POINT('',#1241);
#1243=EDGE_CURVE('E986',#1211,#1242,#1240,.T.);
#1244=ORIENTED_EDGE('',*,*,#1243,.T.);
#1245=DIRECTION('',(-1.,0.,0.));
#1246=VECTOR('',#1245,1.);
#1247=CARTESIAN_POINT('',(1175.95,22.,-15.7500000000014));
#1248=LINE('',#1247,#1246);
#1249=CARTESIAN_POINT('',(1175.95,22.,-15.7500000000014));
#1250=VERTEX_POINT('',#1249);
#1251=EDGE_CURVE('E1029',#1250,#1242,#1248,.T.);
#1252=ORIENTED_EDGE('',*,*,#1251,.F.);
#1253=DIRECTION('',(0.,1.,0.));
#1254=VECTOR('',#1253,1.);
#1255=CARTESIAN_POINT('',(1175.95,22.,-15.7500000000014));
#1256=LINE('',#1255,#1254);
#1257=EDGE_CURVE('E1017',#1219,#1250,#1256,.T.);
#1258=ORIENTED_EDGE('',*,*,#1257,.F.);
#1259=ORIENTED_EDGE('',*,*,#1220,.T.);
#1260=EDGE_LOOP('',(#1244,#1252,#1258,#1259));
#1261=FACE_BOUND('',#1260,.T.);
#1262=ADVANCED_FACE('F1031',(#1261),#1236,.F.);
#1263=CARTESIAN_POINT('',(1175.95,22.,-11.4000000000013));
#1264=DIRECTION('',(0.,-1.,0.));
#1265=DIRECTION('',(0.,0.,-1.));
#1266=AXIS2_PLACEMENT_3D('',#1263,#1264,#1265);
#1267=PLANE('',#1266);
#1268=DIRECTION('',(0.,0.,1.));
#1269=VECTOR('',#1268,1.);
#1270=CARTESIAN_POINT('',(1140.95,22.,-11.4000000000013));
#1271=LINE('',#1270,#1269);
#1272=EDGE_CURVE('E992',#1242,#1047,#1271,.T.);
#1273=ORIENTED_EDGE('',*,*,#1272,.T.);
#1274=ORIENTED_EDGE('',*,*,#1072,.F.);
#1275=DIRECTION('',(0.,0.,1.));
#1276=VECTOR('',#1275,1.);
#1277=CARTESIAN_POINT('',(1175.95,22.,-11.4000000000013));
#1278=LINE('',#1277,#1276);
#1279=EDGE_CURVE('E957',#1250,#1065,#1278,.T.);
#1280=ORIENTED_EDGE('',*,*,#1279,.F.);
#1281=ORIENTED_EDGE('',*,*,#1251,.T.);
#1282=EDGE_LOOP('',(#1273,#1274,#1280,#1281));
#1283=FACE_BOUND('',#1282,.T.);
#1284=ADVANCED_FACE('F1102',(#1283),#1267,.F.);
#1285=CARTESIAN_POINT('',(1175.95,0.,-11.4));
#1286=DIRECTION('',(-1.,0.,0.));
#1287=DIRECTION('',(0.,0.,1.));
#1288=AXIS2_PLACEMENT_3D('',#1285,#1286,#1287);
#1289=PLANE('',#1288);
#1290=ORIENTED_EDGE('',*,*,#1066,.T.);
#1291=ORIENTED_EDGE('',*,*,#1102,.T.);
#1292=ORIENTED_EDGE('',*,*,#1133,.T.);
#1293=ORIENTED_EDGE('',*,*,#1164,.T.);
#1294=ORIENTED_EDGE('',*,*,#1195,.T.);
#1295=ORIENTED_EDGE('',*,*,#1226,.T.);
#1296=ORIENTED_EDGE('',*,*,#1257,.T.);
#1297=ORIENTED_EDGE('',*,*,#1279,.T.);
#1298=EDGE_LOOP('',(#1290,#1291,#1292,#1293,#1294,#1295,#1296,#1297));
#1299=FACE_BOUND('',#1298,.T.);
#1300=ADVANCED_FACE('F1015',(#1299),#1289,.F.);
#1301=CARTESIAN_POINT('',(1140.95,0.,-11.4));
#1302=DIRECTION('',(-1.,0.,0.));
#1303=DIRECTION('',(0.,0.,1.));
#1304=AXIS2_PLACEMENT_3D('',#1301,#1302,#1303);
#1305=PLANE('',#1304);
#1306=ORIENTED_EDGE('',*,*,#1050,.F.);
#1307=ORIENTED_EDGE('',*,*,#1272,.F.);
#1308=ORIENTED_EDGE('',*,*,#1243,.F.);
#1309=ORIENTED_EDGE('',*,*,#1212,.F.);
#1310=ORIENTED_EDGE('',*,*,#1181,.F.);
#1311=ORIENTED_EDGE('',*,*,#1150,.F.);
#1312=ORIENTED_EDGE('',*,*,#1119,.F.);
#1313=ORIENTED_EDGE('',*,*,#1088,.F.);
#1314=EDGE_LOOP('',(#1306,#1307,#1308,#1309,#1310,#1311,#1312,#1313));
#1315=FACE_BOUND('',#1314,.T.);
#1316=ADVANCED_FACE('F1070',(#1315),#1305,.T.);
#1317=CLOSED_SHELL('',(#1076,#1107,#1138,#1169,#1200,#1231,#1262,#1284,#1300,#1316));
#1318=MANIFOLD_SOLID_BREP('B38',#1317);
#1319=CARTESIAN_POINT('',(11.45,2100.,-3.4));
#1320=DIRECTION('',(-1.,0.,0.));
#1321=DIRECTION('',(0.,0.,1.));
#1322=AXIS2_PLACEMENT_3D('',#1319,#1320,#1321);
#1323=PLANE('',#1322);
#1324=DIRECTION('',(0.,0.,-1.));
#1325=VECTOR('',#1324,1.);
#1326=CARTESIAN_POINT('',(11.45,0.,-3.4));
#1327=LINE('',#1326,#1325);
#1328=CARTESIAN_POINT('',(11.45,0.,-3.4));
#1329=VERTEX_POINT('',#1328);
#1330=CARTESIAN_POINT('',(11.45,0.,-11.4));
#1331=VERTEX_POINT('',#1330);
#1332=EDGE_CURVE('E1242',#1329,#1331,#1327,.T.);
#1333=ORIENTED_EDGE('',*,*,#1332,.F.);
#1334=DIRECTION('',(0.,-1.,0.));
#1335=VECTOR('',#1334,1.);
#1336=CARTESIAN_POINT('',(11.45,2100.,-3.4));
#1337=LINE('',#1336,#1335);
#1338=CARTESIAN_POINT('',(11.45,2100.,-3.4));
#1339=VERTEX_POINT('',#1338);
#1340=EDGE_CURVE('E939',#1339,#1329,#1337,.T.);
#1341=ORIENTED_EDGE('',*,*,#1340,.F.);
#1342=DIRECTION('',(0.,0.,-1.));
#1343=VECTOR('',#1342,1.);
#1344=CARTESIAN_POINT('',(11.45,2100.,-3.4));
#1345=LINE('',#1344,#1343);
#1346=CARTESIAN_POINT('',(11.45,2100.,-11.4));
#1347=VERTEX_POINT('',#1346);
#1348=EDGE_CURVE('E1236',#1339,#1347,#1345,.T.);
#1349=ORIENTED_EDGE('',*,*,#1348,.T.);
#1350=DIRECTION('',(0.,-1.,0.));
#1351=VECTOR('',#1350,1.);
#1352=CARTESIAN_POINT('',(11.45,2100.,-11.4));
#1353=LINE('',#1352,#1351);
#1354=EDGE_CURVE('E1181',#1347,#1331,#1353,.T.);
#1355=ORIENTED_EDGE('',*,*,#1354,.T.);
#1356=EDGE_LOOP('',(#1333,#1341,#1349,#1355));
#1357=FACE_BOUND('',#1356,.T.);
#1358=ADVANCED_FACE('F1178',(#1357),#1323,.T.);
#1359=CARTESIAN_POINT('',(11.45,2100.,-3.4));
#1360=DIRECTION('',(0.,0.,1.));
#1361=DIRECTION('',(1.,0.,0.));
#1362=AXIS2_PLACEMENT_3D('',#1359,#1360,#1361);
#1363=PLANE('',#1362);
#1364=DIRECTION('',(-1.,0.,0.));
#1365=VECTOR('',#1364,1.);
#1366=CARTESIAN_POINT('',(11.45,0.,-3.4));
#1367=LINE('',#1366,#1365);
#1368=CARTESIAN_POINT('',(1258.45,0.,-3.4));
#1369=VERTEX_POINT('',#1368);
#1370=EDGE_CURVE('E1238',#1369,#1329,#1367,.T.);
#1371=ORIENTED_EDGE('',*,*,#1370,.F.);
#1372=DIRECTION('',(0.,-1.,0.));
#1373=VECTOR('',#1372,1.);
#1374=CARTESIAN_POINT('',(1258.45,2100.,-3.4));
#1375=LINE('',#1374,#1373);
#1376=CARTESIAN_POINT('',(1258.45,2100.,-3.4));
#1377=VERTEX_POINT('',#1376);
#1378=EDGE_CURVE('E1187',#1377,#1369,#1375,.T.);
#1379=ORIENTED_EDGE('',*,*,#1378,.F.);
#1380=DIRECTION('',(-1.,0.,0.));
#1381=VECTOR('',#1380,1.);
#1382=CARTESIAN_POINT('',(11.45,2100.,-3.4));
#1383=LINE('',#1382,#1381);
#1384=EDGE_CURVE('E1233',#1377,#1339,#1383,.T.);
#1385=ORIENTED_EDGE('',*,*,#1384,.T.);
#1386=ORIENTED_EDGE('',*,*,#1340,.T.);
#1387=EDGE_LOOP('',(#1371,#1379,#1385,#1386));
#1388=FACE_BOUND('',#1387,.T.);
#1389=ADVANCED_FACE('F1252',(#1388),#1363,.T.);
#1390=CARTESIAN_POINT('',(1258.45,2100.,-3.4));
#1391=DIRECTION('',(1.,0.,0.));
#1392=DIRECTION('',(0.,0.,-1.));
#1393=AXIS2_PLACEMENT_3D('',#1390,#1391,#1392);
#1394=PLANE('',#1393);
#1395=DIRECTION('',(0.,0.,1.));
#1396=VECTOR('',#1395,1.);
#1397=CARTESIAN_POINT('',(1258.45,0.,-3.4));
#1398=LINE('',#1397,#1396);
#1399=CARTESIAN_POINT('',(1258.45,0.,-11.4));
#1400=VERTEX_POINT('',#1399);
#1401=EDGE_CURVE('E1228',#1400,#1369,#1398,.T.);
#1402=ORIENTED_EDGE('',*,*,#1401,.F.);
#1403=DIRECTION('',(0.,-1.,0.));
#1404=VECTOR('',#1403,1.);
#1405=CARTESIAN_POINT('',(1258.45,2100.,-11.4));
#1406=LINE('',#1405,#1404);
#1407=CARTESIAN_POINT('',(1258.45,2100.,-11.4));
#1408=VERTEX_POINT('',#1407);
#1409=EDGE_CURVE('E1223',#1408,#1400,#1406,.T.);
#1410=ORIENTED_EDGE('',*,*,#1409,.F.);
#1411=DIRECTION('',(0.,0.,1.));
#1412=VECTOR('',#1411,1.);
#1413=CARTESIAN_POINT('',(1258.45,2100.,-3.4));
#1414=LINE('',#1413,#1412);
#1415=EDGE_CURVE('E1226',#1408,#1377,#1414,.T.);
#1416=ORIENTED_EDGE('',*,*,#1415,.T.);
#1417=ORIENTED_EDGE('',*,*,#1378,.T.);
#1418=EDGE_LOOP('',(#1402,#1410,#1416,#1417));
#1419=FACE_BOUND('',#1418,.T.);
#1420=ADVANCED_FACE('F1225',(#1419),#1394,.T.);
#1421=CARTESIAN_POINT('',(11.45,2100.,-11.4));
#1422=DIRECTION('',(0.,0.,-1.));
#1423=DIRECTION('',(-1.,0.,0.));
#1424=AXIS2_PLACEMENT_3D('',#1421,#1422,#1423);
#1425=PLANE('',#1424);
#1426=DIRECTION('',(1.,0.,0.));
#1427=VECTOR('',#1426,1.);
#1428=CARTESIAN_POINT('',(11.45,0.,-11.4));
#1429=LINE('',#1428,#1427);
#1430=EDGE_CURVE('E1245',#1331,#1400,#1429,.T.);
#1431=ORIENTED_EDGE('',*,*,#1430,.F.);
#1432=ORIENTED_EDGE('',*,*,#1354,.F.);
#1433=DIRECTION('',(1.,0.,0.));
#1434=VECTOR('',#1433,1.);
#1435=CARTESIAN_POINT('',(11.45,2100.,-11.4));
#1436=LINE('',#1435,#1434);
#1437=EDGE_CURVE('E1232',#1347,#1408,#1436,.T.);
#1438=ORIENTED_EDGE('',*,*,#1437,.T.);
#1439=ORIENTED_EDGE('',*,*,#1409,.T.);
#1440=EDGE_LOOP('',(#1431,#1432,#1438,#1439));
#1441=FACE_BOUND('',#1440,.T.);
#1442=ADVANCED_FACE('F1235',(#1441),#1425,.T.);
#1443=CARTESIAN_POINT('',(11.45,2100.,-11.4));
#1444=DIRECTION('',(0.,-1.,0.));
#1445=DIRECTION('',(0.,0.,-1.));
#1446=AXIS2_PLACEMENT_3D('',#1443,#1444,#1445);
#1447=PLANE('',#1446);
#1448=ORIENTED_EDGE('',*,*,#1348,.F.);
#1449=ORIENTED_EDGE('',*,*,#1384,.F.);
#1450=ORIENTED_EDGE('',*,*,#1415,.F.);
#1451=ORIENTED_EDGE('',*,*,#1437,.F.);
#1452=EDGE_LOOP('',(#1448,#1449,#1450,#1451));
#1453=FACE_BOUND('',#1452,.T.);
#1454=ADVANCED_FACE('F1231',(#1453),#1447,.F.);
#1455=CARTESIAN_POINT('',(11.45,0.,-11.4));
#1456=DIRECTION('',(0.,-1.,0.));
#1457=DIRECTION('',(0.,0.,-1.));
#1458=AXIS2_PLACEMENT_3D('',#1455,#1456,#1457);
#1459=PLANE('',#1458);
#1460=ORIENTED_EDGE('',*,*,#1332,.T.);
#1461=ORIENTED_EDGE('',*,*,#1430,.T.);
#1462=ORIENTED_EDGE('',*,*,#1401,.T.);
#1463=ORIENTED_EDGE('',*,*,#1370,.T.);
#1464=EDGE_LOOP('',(#1460,#1461,#1462,#1463));
#1465=FACE_BOUND('',#1464,.T.);
#1466=ADVANCED_FACE('F1251',(#1465),#1459,.T.);
#1467=CLOSED_SHELL('',(#1358,#1389,#1420,#1442,#1454,#1466));
#1468=MANIFOLD_SOLID_BREP('B310',#1467);
#1469=CARTESIAN_POINT('',(0.,2100.,-13.3));
#1470=DIRECTION('',(0.,0.,1.));
#1471=DIRECTION('',(1.,0.,0.));
#1472=AXIS2_PLACEMENT_3D('',#1469,#1470,#1471);
#1473=PLANE('',#1472);
#1474=DIRECTION('',(0.,-1.,0.));
#1475=VECTOR('',#1474,1.);
#1476=CARTESIAN_POINT('',(25.,2100.,-13.3));
#1477=LINE('',#1476,#1475);
#1478=CARTESIAN_POINT('',(25.,2103.,-13.3));
#1479=VERTEX_POINT('',#1478);
#1480=CARTESIAN_POINT('',(25.,-3.,-13.3));
#1481=VERTEX_POINT('',#1480);
#1482=EDGE_CURVE('E1376',#1479,#1481,#1477,.T.);
#1483=ORIENTED_EDGE('',*,*,#1482,.T.);
#1484=DIRECTION('',(1.,0.,0.));
#1485=VECTOR('',#1484,1.);
#1486=CARTESIAN_POINT('',(25.,-3.,-13.3));
#1487=LINE('',#1486,#1485);
#1488=CARTESIAN_POINT('',(0.,-3.,-13.3));
#1489=VERTEX_POINT('',#1488);
#1490=EDGE_CURVE('E1375',#1489,#1481,#1487,.T.);
#1491=ORIENTED_EDGE('',*,*,#1490,.F.);
#1492=DIRECTION('',(0.,-1.,0.));
#1493=VECTOR('',#1492,1.);
#1494=CARTESIAN_POINT('',(0.,2100.,-13.3));
#1495=LINE('',#1494,#1493);
#1496=CARTESIAN_POINT('',(0.,2103.,-13.3));
#1497=VERTEX_POINT('',#1496);
#1498=EDGE_CURVE('E1176',#1497,#1489,#1495,.T.);
#1499=ORIENTED_EDGE('',*,*,#1498,.F.);
#1500=DIRECTION('',(-1.,0.,0.));
#1501=VECTOR('',#1500,1.);
#1502=CARTESIAN_POINT('',(25.,2103.,-13.3));
#1503=LINE('',#1502,#1501);
#1504=EDGE_CURVE('E1403',#1479,#1497,#1503,.T.);
#1505=ORIENTED_EDGE('',*,*,#1504,.F.);
#1506=EDGE_LOOP('',(#1483,#1491,#1499,#1505));
#1507=FACE_BOUND('',#1506,.T.);
#1508=ADVANCED_FACE('F1302',(#1507),#1473,.F.);
#1509=CARTESIAN_POINT('',(0.,2100.,0.));
#1510=DIRECTION('',(1.,0.,0.));
#1511=DIRECTION('',(0.,0.,-1.));
#1512=AXIS2_PLACEMENT_3D('',#1509,#1510,#1511);
#1513=PLANE('',#1512);
#1514=ORIENTED_EDGE('',*,*,#1498,.T.);
#1515=DIRECTION('',(0.,0.,-1.));
#1516=VECTOR('',#1515,1.);
#1517=CARTESIAN_POINT('',(0.,-3.,-13.3));
#1518=LINE('',#1517,#1516);
#1519=CARTESIAN_POINT('',(0.,-3.,0.));
#1520=VERTEX_POINT('',#1519);
#1521=EDGE_CURVE('E1368',#1520,#1489,#1518,.T.);
#1522=ORIENTED_EDGE('',*,*,#1521,.F.);
#1523=DIRECTION('',(0.,-1.,0.));
#1524=VECTOR('',#1523,1.);
#1525=CARTESIAN_POINT('',(0.,2100.,0.));
#1526=LINE('',#1525,#1524);
#1527=CARTESIAN_POINT('',(0.,2103.,0.));
#1528=VERTEX_POINT('',#1527);
#1529=EDGE_CURVE('E1312',#1528,#1520,#1526,.T.);
#1530=ORIENTED_EDGE('',*,*,#1529,.F.);
#1531=DIRECTION('',(0.,0.,1.));
#1532=VECTOR('',#1531,1.);
#1533=CARTESIAN_POINT('',(0.,2103.,-13.3));
#1534=LINE('',#1533,#1532);
#1535=EDGE_CURVE('E1370',#1497,#1528,#1534,.T.);
#1536=ORIENTED_EDGE('',*,*,#1535,.F.);
#1537=EDGE_LOOP('',(#1514,#1522,#1530,#1536));
#1538=FACE_BOUND('',#1537,.T.);
#1539=ADVANCED_FACE('F1366',(#1538),#1513,.F.);
#1540=CARTESIAN_POINT('',(25.,2100.,0.));
#1541=DIRECTION('',(0.,0.,-1.));
#1542=DIRECTION('',(-1.,0.,0.));
#1543=AXIS2_PLACEMENT_3D('',#1540,#1541,#1542);
#1544=PLANE('',#1543);
#1545=ORIENTED_EDGE('',*,*,#1529,.T.);
#1546=DIRECTION('',(-1.,0.,0.));
#1547=VECTOR('',#1546,1.);
#1548=CARTESIAN_POINT('',(0.,-3.,0.));
#1549=LINE('',#1548,#1547);
#1550=CARTESIAN_POINT('',(25.,-3.,0.));
#1551=VERTEX_POINT('',#1550);
#1552=EDGE_CURVE('E1385',#1551,#1520,#1549,.T.);
#1553=ORIENTED_EDGE('',*,*,#1552,.F.);
#1554=DIRECTION('',(0.,-1.,0.));
#1555=VECTOR('',#1554,1.);
#1556=CARTESIAN_POINT('',(25.,2100.,0.));
#1557=LINE('',#1556,#1555);
#1558=CARTESIAN_POINT('',(25.,2103.,0.));
#1559=VERTEX_POINT('',#1558);
#1560=EDGE_CURVE('E1427',#1559,#1551,#1557,.T.);
#1561=ORIENTED_EDGE('',*,*,#1560,.F.);
#1562=DIRECTION('',(1.,0.,0.));
#1563=VECTOR('',#1562,1.);
#1564=CARTESIAN_POINT('',(0.,2103.,0.));
#1565=LINE('',#1564,#1563);
#1566=EDGE_CURVE('E1397',#1528,#1559,#1565,.T.);
#1567=ORIENTED_EDGE('',*,*,#1566,.F.);
#1568=EDGE_LOOP('',(#1545,#1553,#1561,#1567));
#1569=FACE_BOUND('',#1568,.T.);
#1570=ADVANCED_FACE('F1476',(#1569),#1544,.F.);
#1571=CARTESIAN_POINT('',(11.45,2100.,-3.4));
#1572=DIRECTION('',(0.,0.,1.));
#1573=DIRECTION('',(1.,0.,0.));
#1574=AXIS2_PLACEMENT_3D('',#1571,#1572,#1573);
#1575=PLANE('',#1574);
#1576=DIRECTION('',(-1.,0.,0.));
#1577=VECTOR('',#1576,1.);
#1578=CARTESIAN_POINT('',(11.45,0.,-3.4));
#1579=LINE('',#1578,#1577);
#1580=CARTESIAN_POINT('',(25.,0.,-3.4));
#1581=VERTEX_POINT('',#1580);
#1582=CARTESIAN_POINT('',(11.45,0.,-3.4));
#1583=VERTEX_POINT('',#1582);
#1584=EDGE_CURVE('E1405',#1581,#1583,#1579,.T.);
#1585=ORIENTED_EDGE('',*,*,#1584,.T.);
#1586=DIRECTION('',(0.,-1.,0.));
#1587=VECTOR('',#1586,1.);
#1588=CARTESIAN_POINT('',(11.45,2100.,-3.4));
#1589=LINE('',#1588,#1587);
#1590=CARTESIAN_POINT('',(11.45,2100.,-3.4));
#1591=VERTEX_POINT('',#1590);
#1592=EDGE_CURVE('E1428',#1591,#1583,#1589,.T.);
#1593=ORIENTED_EDGE('',*,*,#1592,.F.);
#1594=DIRECTION('',(-1.,0.,0.));
#1595=VECTOR('',#1594,1.);
#1596=CARTESIAN_POINT('',(11.45,2100.,-3.4));
#1597=LINE('',#1596,#1595);
#1598=CARTESIAN_POINT('',(25.,2100.,-3.4));
#1599=VERTEX_POINT('',#1598);
#1600=EDGE_CURVE('E1414',#1599,#1591,#1597,.T.);
#1601=ORIENTED_EDGE('',*,*,#1600,.F.);
#1602=DIRECTION('',(0.,-1.,0.));
#1603=VECTOR('',#1602,1.);
#1604=CARTESIAN_POINT('',(25.,2100.,-3.4));
#1605=LINE('',#1604,#1603);
#1606=EDGE_CURVE('E1424',#1599,#1581,#1605,.T.);
#1607=ORIENTED_EDGE('',*,*,#1606,.T.);
#1608=EDGE_LOOP('',(#1585,#1593,#1601,#1607));
#1609=FACE_BOUND('',#1608,.T.);
#1610=ADVANCED_FACE('F1457',(#1609),#1575,.F.);
#1611=CARTESIAN_POINT('',(11.45,2100.,-11.4));
#1612=DIRECTION('',(-1.,0.,0.));
#1613=DIRECTION('',(0.,0.,1.));
#1614=AXIS2_PLACEMENT_3D('',#1611,#1612,#1613);
#1615=PLANE('',#1614);
#1616=DIRECTION('',(0.,0.,-1.));
#1617=VECTOR('',#1616,1.);
#1618=CARTESIAN_POINT('',(11.45,0.,-11.4));
#1619=LINE('',#1618,#1617);
#1620=CARTESIAN_POINT('',(11.45,0.,-11.4));
#1621=VERTEX_POINT('',#1620);
#1622=EDGE_CURVE('E1417',#1583,#1621,#1619,.T.);
#1623=ORIENTED_EDGE('',*,*,#1622,.T.);
#1624=DIRECTION('',(0.,-1.,0.));
#1625=VECTOR('',#1624,1.);
#1626=CARTESIAN_POINT('',(11.45,2100.,-11.4));
#1627=LINE('',#1626,#1625);
#1628=CARTESIAN_POINT('',(11.45,2100.,-11.4));
#1629=VERTEX_POINT('',#1628);
#1630=EDGE_CURVE('E1320',#1629,#1621,#1627,.T.);
#1631=ORIENTED_EDGE('',*,*,#1630,.F.);
#1632=DIRECTION('',(0.,0.,-1.));
#1633=VECTOR('',#1632,1.);
#1634=CARTESIAN_POINT('',(11.45,2100.,-11.4));
#1635=LINE('',#1634,#1633);
#1636=EDGE_CURVE('E1410',#1591,#1629,#1635,.T.);
#1637=ORIENTED_EDGE('',*,*,#1636,.F.);
#1638=ORIENTED_EDGE('',*,*,#1592,.T.);
#1639=EDGE_LOOP('',(#1623,#1631,#1637,#1638));
#1640=FACE_BOUND('',#1639,.T.);
#1641=ADVANCED_FACE('F1455',(#1640),#1615,.F.);
#1642=CARTESIAN_POINT('',(25.,2100.,-11.4));
#1643=DIRECTION('',(0.,0.,-1.));
#1644=DIRECTION('',(-1.,0.,0.));
#1645=AXIS2_PLACEMENT_3D('',#1642,#1643,#1644);
#1646=PLANE('',#1645);
#1647=DIRECTION('',(1.,0.,0.));
#1648=VECTOR('',#1647,1.);
#1649=CARTESIAN_POINT('',(25.,0.,-11.4));
#1650=LINE('',#1649,#1648);
#1651=CARTESIAN_POINT('',(25.,0.,-11.4));
#1652=VERTEX_POINT('',#1651);
#1653=EDGE_CURVE('E1305',#1621,#1652,#1650,.T.);
#1654=ORIENTED_EDGE('',*,*,#1653,.T.);
#1655=DIRECTION('',(0.,-1.,0.));
#1656=VECTOR('',#1655,1.);
#1657=CARTESIAN_POINT('',(25.,2100.,-11.4));
#1658=LINE('',#1657,#1656);
#1659=CARTESIAN_POINT('',(25.,2100.,-11.4));
#1660=VERTEX_POINT('',#1659);
#1661=EDGE_CURVE('E1444',#1660,#1652,#1658,.T.);
#1662=ORIENTED_EDGE('',*,*,#1661,.F.);
#1663=DIRECTION('',(1.,0.,0.));
#1664=VECTOR('',#1663,1.);
#1665=CARTESIAN_POINT('',(25.,2100.,-11.4));
#1666=LINE('',#1665,#1664);
#1667=EDGE_CURVE('E1413',#1629,#1660,#1666,.T.);
#1668=ORIENTED_EDGE('',*,*,#1667,.F.);
#1669=ORIENTED_EDGE('',*,*,#1630,.T.);
#1670=EDGE_LOOP('',(#1654,#1662,#1668,#1669));
#1671=FACE_BOUND('',#1670,.T.);
#1672=ADVANCED_FACE('F1443',(#1671),#1646,.F.);
#1673=CARTESIAN_POINT('',(25.,2100.,-13.3));
#1674=DIRECTION('',(-1.,0.,0.));
#1675=DIRECTION('',(0.,0.,1.));
#1676=AXIS2_PLACEMENT_3D('',#1673,#1674,#1675);
#1677=PLANE('',#1676);
#1678=DIRECTION('',(0.,0.,1.));
#1679=VECTOR('',#1678,1.);
#1680=CARTESIAN_POINT('',(25.,-3.,0.));
#1681=LINE('',#1680,#1679);
#1682=EDGE_CURVE('E1380',#1481,#1551,#1681,.T.);
#1683=ORIENTED_EDGE('',*,*,#1682,.F.);
#1684=ORIENTED_EDGE('',*,*,#1482,.F.);
#1685=DIRECTION('',(0.,0.,-1.));
#1686=VECTOR('',#1685,1.);
#1687=CARTESIAN_POINT('',(25.,2103.,0.));
#1688=LINE('',#1687,#1686);
#1689=EDGE_CURVE('E1400',#1559,#1479,#1688,.T.);
#1690=ORIENTED_EDGE('',*,*,#1689,.F.);
#1691=ORIENTED_EDGE('',*,*,#1560,.T.);
#1692=EDGE_LOOP('',(#1683,#1684,#1690,#1691));
#1693=FACE_BOUND('',#1692,.T.);
#1694=ORIENTED_EDGE('',*,*,#1661,.T.);
#1695=DIRECTION('',(0.,0.,1.));
#1696=VECTOR('',#1695,1.);
#1697=CARTESIAN_POINT('',(25.,0.,0.));
#1698=LINE('',#1697,#1696);
#1699=EDGE_CURVE('E1386',#1652,#1581,#1698,.T.);
#1700=ORIENTED_EDGE('',*,*,#1699,.T.);
#1701=ORIENTED_EDGE('',*,*,#1606,.F.);
#1702=DIRECTION('',(0.,0.,-1.));
#1703=VECTOR('',#1702,1.);
#1704=CARTESIAN_POINT('',(25.,2100.,0.));
#1705=LINE('',#1704,#1703);
#1706=EDGE_CURVE('E1393',#1599,#1660,#1705,.T.);
#1707=ORIENTED_EDGE('',*,*,#1706,.T.);
#1708=EDGE_LOOP('',(#1694,#1700,#1701,#1707));
#1709=FACE_BOUND('',#1708,.T.);
#1710=ADVANCED_FACE('F1447',(#1693,#1709),#1677,.F.);
#1711=CARTESIAN_POINT('',(0.,2100.,0.));
#1712=DIRECTION('',(0.,1.,0.));
#1713=DIRECTION('',(0.,0.,1.));
#1714=AXIS2_PLACEMENT_3D('',#1711,#1712,#1713);
#1715=PLANE('',#1714);
#1716=ORIENTED_EDGE('',*,*,#1706,.F.);
#1717=ORIENTED_EDGE('',*,*,#1600,.T.);
#1718=ORIENTED_EDGE('',*,*,#1636,.T.);
#1719=ORIENTED_EDGE('',*,*,#1667,.T.);
#1720=EDGE_LOOP('',(#1716,#1717,#1718,#1719));
#1721=FACE_BOUND('',#1720,.T.);
#1722=ADVANCED_FACE('F1459',(#1721),#1715,.F.);
#1723=CARTESIAN_POINT('',(0.,2103.,0.));
#1724=DIRECTION('',(0.,1.,0.));
#1725=DIRECTION('',(0.,0.,1.));
#1726=AXIS2_PLACEMENT_3D('',#1723,#1724,#1725);
#1727=PLANE('',#1726);
#1728=ORIENTED_EDGE('',*,*,#1535,.T.);
#1729=ORIENTED_EDGE('',*,*,#1566,.T.);
#1730=ORIENTED_EDGE('',*,*,#1689,.T.);
#1731=ORIENTED_EDGE('',*,*,#1504,.T.);
#1732=EDGE_LOOP('',(#1728,#1729,#1730,#1731));
#1733=FACE_BOUND('',#1732,.T.);
#1734=ADVANCED_FACE('F1461',(#1733),#1727,.T.);
#1735=CARTESIAN_POINT('',(0.,0.,0.));
#1736=DIRECTION('',(0.,1.,0.));
#1737=DIRECTION('',(0.,0.,1.));
#1738=AXIS2_PLACEMENT_3D('',#1735,#1736,#1737);
#1739=PLANE('',#1738);
#1740=ORIENTED_EDGE('',*,*,#1653,.F.);
#1741=ORIENTED_EDGE('',*,*,#1622,.F.);
#1742=ORIENTED_EDGE('',*,*,#1584,.F.);
#1743=ORIENTED_EDGE('',*,*,#1699,.F.);
#1744=EDGE_LOOP('',(#1740,#1741,#1742,#1743));
#1745=FACE_BOUND('',#1744,.T.);
#1746=ADVANCED_FACE('F1467',(#1745),#1739,.T.);
#1747=CARTESIAN_POINT('',(0.,-3.,0.));
#1748=DIRECTION('',(0.,1.,0.));
#1749=DIRECTION('',(0.,0.,1.));
#1750=AXIS2_PLACEMENT_3D('',#1747,#1748,#1749);
#1751=PLANE('',#1750);
#1752=ORIENTED_EDGE('',*,*,#1521,.T.);
#1753=ORIENTED_EDGE('',*,*,#1490,.T.);
#1754=ORIENTED_EDGE('',*,*,#1682,.T.);
#1755=ORIENTED_EDGE('',*,*,#1552,.T.);
#1756=EDGE_LOOP('',(#1752,#1753,#1754,#1755));
#1757=FACE_BOUND('',#1756,.T.);
#1758=ADVANCED_FACE('F1383',(#1757),#1751,.F.);
#1759=CLOSED_SHELL('',(#1508,#1539,#1570,#1610,#1641,#1672,#1710,#1722,#1734,#1746,#1758));
#1760=MANIFOLD_SOLID_BREP('B933',#1759);
#1761=ADVANCED_BREP_SHAPE_REPRESENTATION('',(#18,#300,#1036,#1318,#1468,#1760),#14);
#1762=SHAPE_DEFINITION_REPRESENTATION(#9,#1761);
ENDSEC;
END-ISO-10303-21;
